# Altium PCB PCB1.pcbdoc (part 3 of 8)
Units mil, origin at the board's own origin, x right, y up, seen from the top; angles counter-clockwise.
Board outline 5129 x 4161 mil, 8 copper layers (Top Layer, GND1, 内层2, VCC, 内层4, Inner5, GND2, Bottom Layer); 495 components, 453 nets, 2562 pads, 1123 vias.

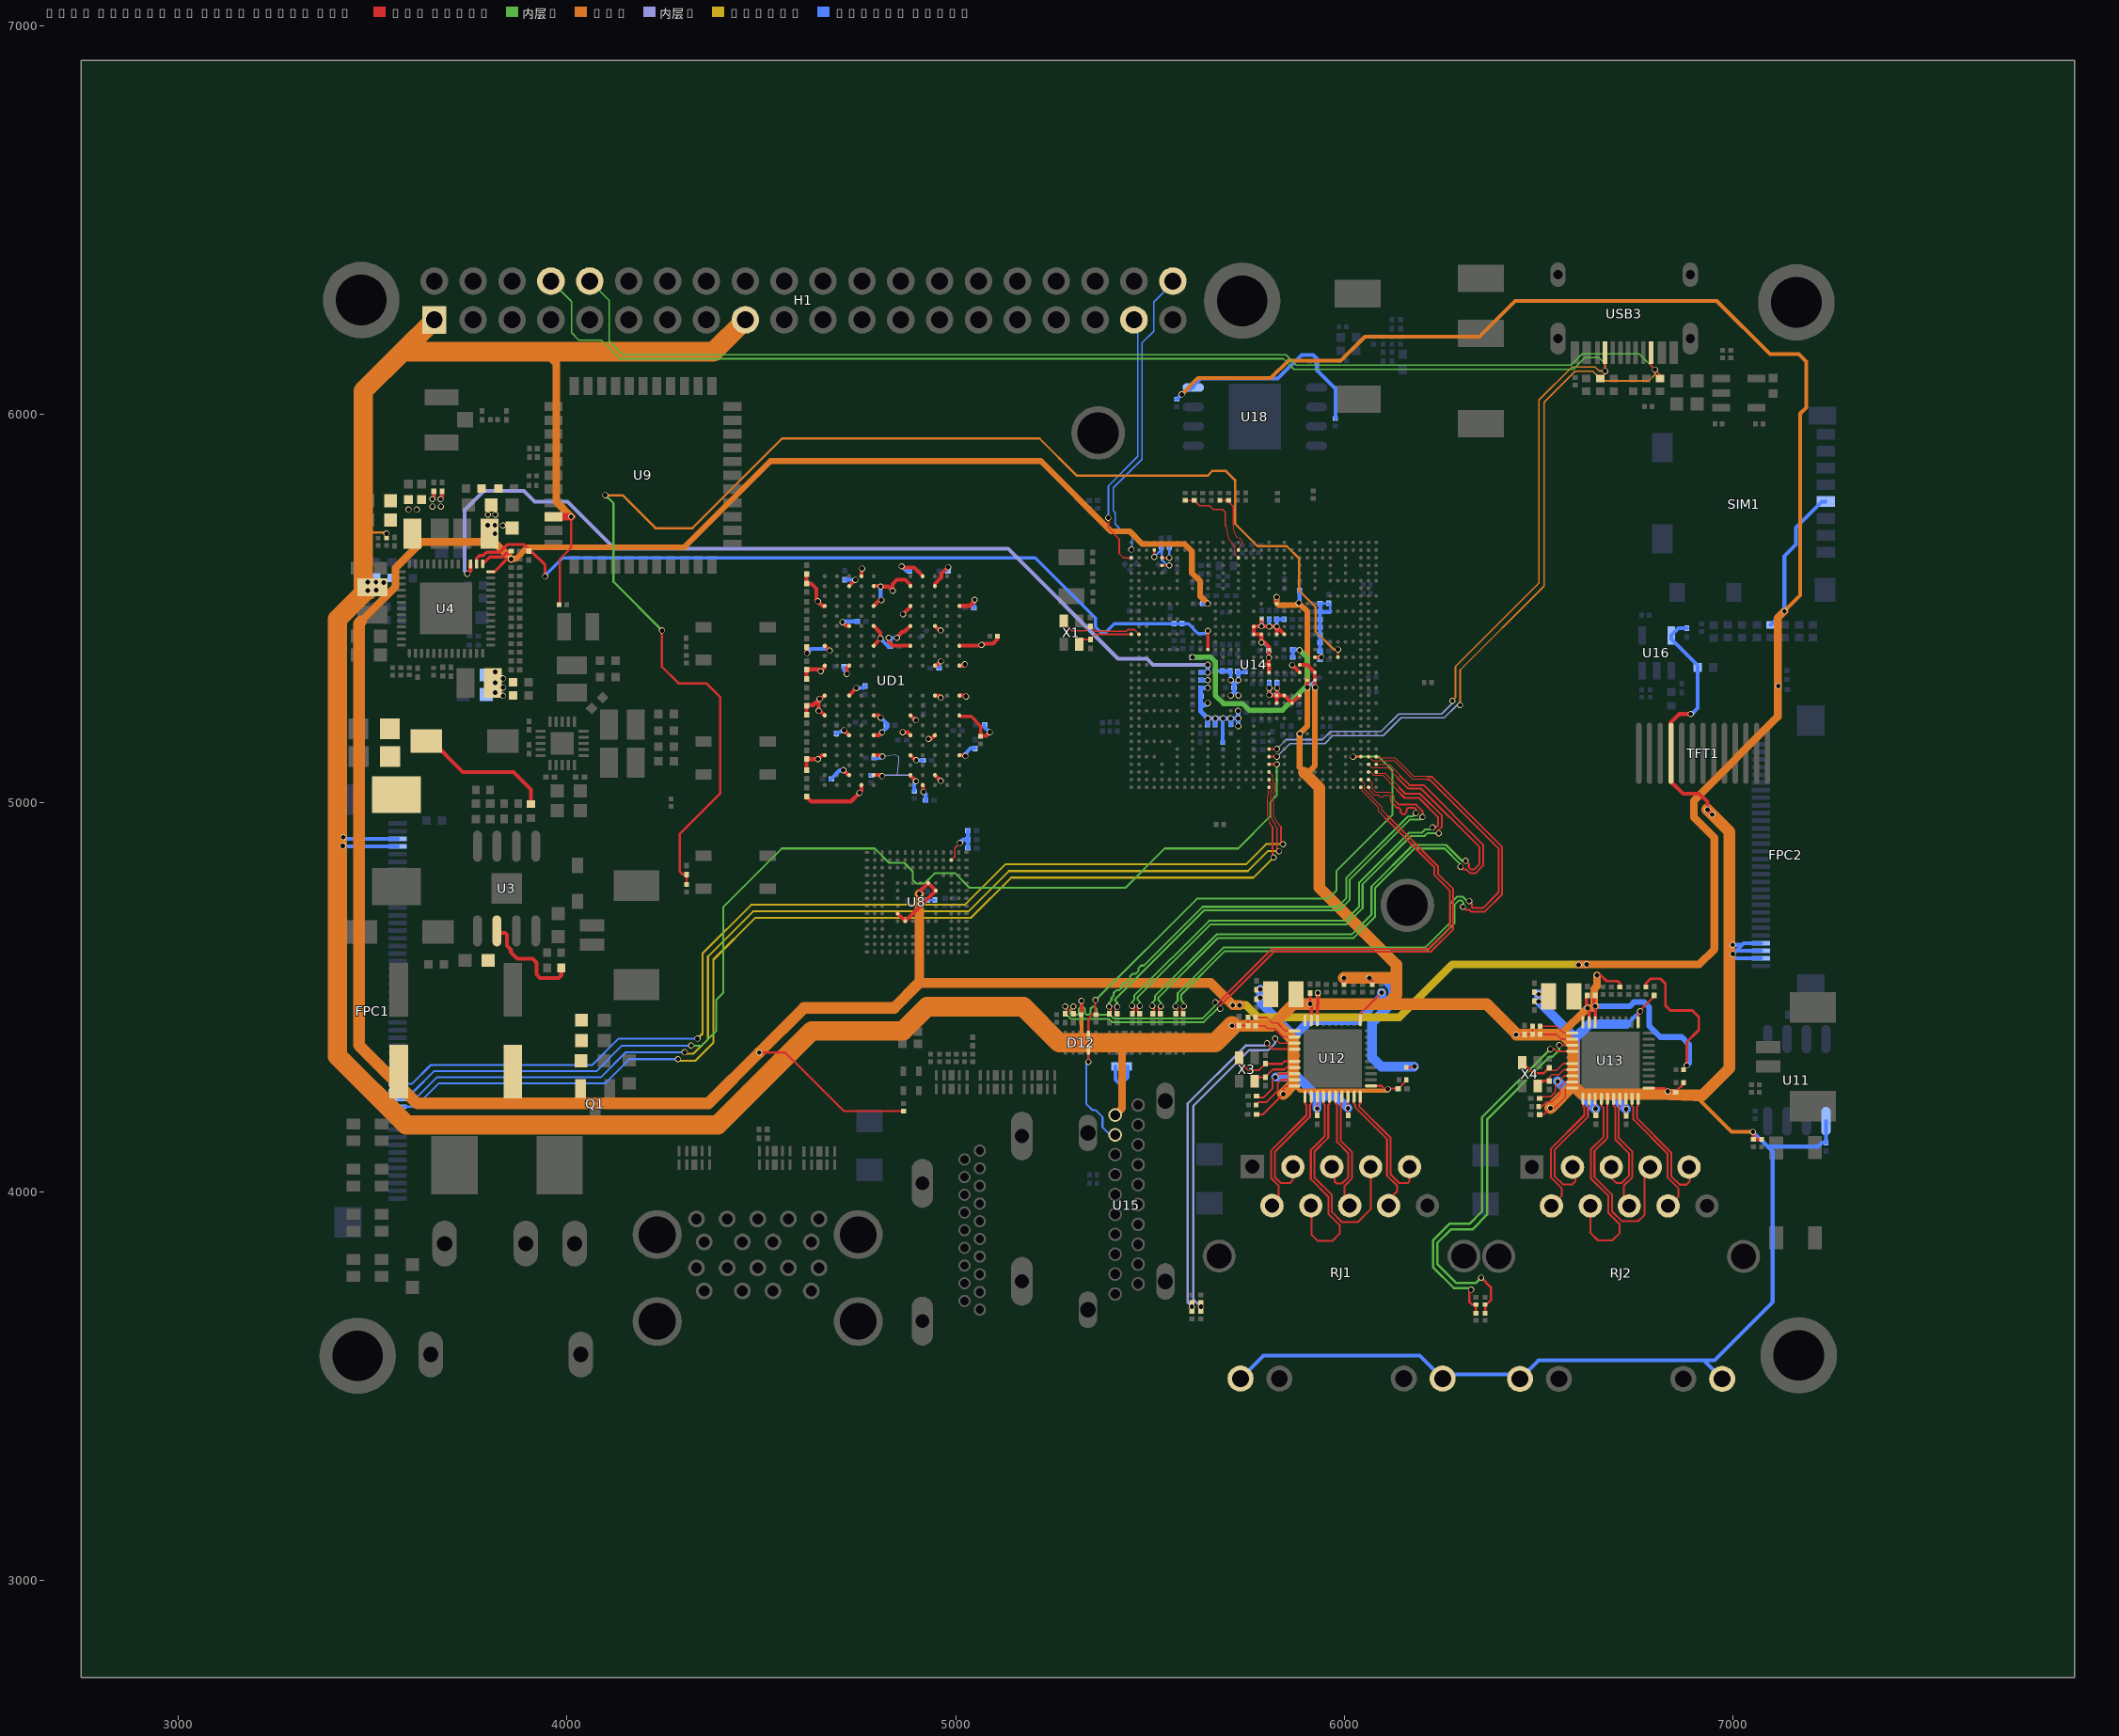
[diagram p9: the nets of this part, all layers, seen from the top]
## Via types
v1: diameter 15.75, hole 11.8, Top Layer to Bottom Layer, 496 vias
v2: diameter 15.7, hole 11.8, Top Layer to Bottom Layer, 335 vias
v3: diameter 15.75, hole 11.81, Top Layer to Bottom Layer, 279 vias
v4: diameter 24, hole 12, Top Layer to Bottom Layer, 13 vias

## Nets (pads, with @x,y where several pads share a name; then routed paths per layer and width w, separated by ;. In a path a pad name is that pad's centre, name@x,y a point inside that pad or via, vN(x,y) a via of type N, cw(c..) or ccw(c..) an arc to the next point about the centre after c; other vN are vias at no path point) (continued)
CLDO3: C64.2 C102.2 C228.1 C229.2 C230.2 C234.1 C235.2 C236.2 D20.1 R47.1 R73.2 R74.2 R75.2 SIM1.4 U4.26 U8.E6 U8.F5 U8.J10 U8.K9 U14.AC9 U18.8 | length 12994.8
  Top Layer w5: v2(4495,4358) 4562,4358 4712.51,4207.49 R47.1@4866,4207.49
  Top Layer w8: U4.26@3803.98,5594.97 3813.97,5594.97 3847,5628 v2(3856.5,5628)
  Top Layer w10: U8.K9@4850.78,4715.48 U8.J10@4870.48,4695.78 4945.65,4770.96 ; v2(4907,4766) 4907,4771.69 U8.F5@4929.52,4794.22 4945.65,4778.09 4945.65,4770.96 ; U8.E6@4949.22,4774.52 4945.65,4770.96
  VCC w10: v2(5581.59,6051.1) 5623.49,6093 5811,6093 5856,6138 5991,6138 6053,6200 6348,6200 6440,6292 6958,6292 7095,6155 7169,6155 7188,6136 7188,6017 7173,6002 7173,5534.4 v1(7132,5493.4)
  VCC w15: v2(3856.5,5628) 3869,5628 3899,5658 4302,5658 4524,5880 5219,5880 5400,5699 5448,5699 5481,5666 5589.33,5666 5608,5647.33 5608,5592 5629,5571 5629,5532.82 v2@5648.87,5512.95
  VCC w20: 3470,5467 3559,5556 3559,5605 3625.75,5671.75 3812.75,5671.75 v2(3856.5,5628) ; v2(6603,4584) 6604,4585 v2(6623.08,4585) 6913,4585 6952,4624 6952,4910 6899,4963 6899,5006 7115,5222 7115,5476.4 v1(7132,5493.4)
  VCC w25: v2(4907,4766) 4907,4538 4906,4537 5656,4537 v2(5713,4480) v2(5731,4480)
  VCC w30: 3470,5467 3465,5462 3465,4377 3615,4227 4364,4227 v2(4495,4358) 4610,4473 4842,4473 4906,4537
  Inner5 w20: v2(5713,4480) v2(5731,4480) 5747,4480 5778,4449 6142,4449 6278,4585 v2(6623.08,4585)
  Bottom Layer w6: v2(4907,4766) 4922.75,4750.25 C229.2@4927.75,4750.25 C235.2@4946.75,4750.25 ; v2(7116.5,5301) C228.1@7116.5,5318 C234.1@7116.5,5341
  Bottom Layer w10: C230.2@4899,4749 4899,4758 v2(4907,4766) ; R75.2@5569,6038.51 v2(5581.59,6051.1) 5599.49,6069 U18.8@5607,6069 ; U18.8@5603,6065 U18.8@5607,6069 ; U18.8@5611.23,6069 U18.8@5607,6069 ; C102.2@5636,5513 v2(5648.82,5513) ; R74.2@5977,5989.51 5977,6066 5929.51,6113.49 R73.2@5929.51,6135 5929.51,6143.49 5920,6153 5890,6153 5829,6092 5630,6092 U18.8@5607,6069 ; D20.1@7097,5458.4 v1(7132,5493.4) 7132,5635 7162,5665 7162,5709 7228.4,5775.4 SIM1.4@7238.14,5775.4
CLDO4: C66.2 U4.27 | length 86.4
  Top Layer w8: U4.27@3783.61,5615.33 3801.27,5633 3834,5633 3844,5643 3851.5,5643 C66.2@3856.5,5648
CPUSLDO: C13.1 C14.1 C35.2 U4.28 U14.AC15 | length 2148.2
  Top Layer w8: U4.28@3767.85,5615.33 3768,5615.49 3768,5630 3775,5637 3785,5637 3793,5645 3827,5645 3847,5665 3889.88,5665 3901,5653.88 3901,5649 C35.2@3902,5648 3908,5648 3944,5612 v2(3944,5583) ; U14.AC15@5648.87,5394.84 v2(5648.87,5443)
  Bottom Layer w8: v2(3944,5583) 3944,5586 3989,5631 5205,5631 5360,5476 5360,5453 5373,5440 5387,5440 5408,5461 5599,5461 5624,5436 5641.87,5436 v2(5648.87,5443)
CPUX-RX: D30.2 H1.10 U14.R29 USB3.B8 | length 4759
  Top Layer w5: U14.R29@5806.35,5119.25 v1(5826.35,5119.25) ; USB3.B8@6788.9,6158.7 6788.9,6125.1 v2(6799.2,6114.8) 6812,6102 D30.2@6812,6092.4
  内层2 w4: H1.10@4059,6343 4109,6293 4109,6188 4144,6153 5850,6153 5876,6127 6583,6127 6612,6156 6758,6156 v2@6799,6115
  VCC w4: v2(6298,5252) 6298,5342 6514,5558 6514,6031 6594,6111 6639,6111 6664,6086 6783,6086 6799.2,6102.2 v2(6799.2,6114.8)
  内层4 w4: v1(5826.35,5119.25) 5860.1,5153 5950,5153 5970,5173 6100,5173 6146,5219 6257,5219 6290,5252 v2(6298,5252)
CPUX-TX: D27.2 H1.8 U14.R28 USB3.A8 | length 4564.4
  Top Layer w5: U14.R28@5806.35,5138.93 v1(5826.35,5138.93) ; D27.2@6658,6092.4 6670.79,6105.19 USB3.A8@6670.79,6158.7
  内层2 w4: H1.8@3959,6343 4012,6290 4012,6210 4031,6191 4089,6191 4137,6143 5843,6143 5870,6116 6589,6116 6619,6146 6655,6146 6670.79,6130.21 v2(6670.79,6111.36)
  VCC w4: v2(6278,5263) 6286,5271 6286,5351 6501,5566 6501,6037 6586,6122 6645,6122 6655.64,6111.36 v2(6670.79,6111.36)
  内层4 w4: v1(5826.35,5138.93) 5850.43,5163 5944,5163 5965,5184 6095,5184 6140,5229 6250,5229 6278,5257 v2(6278,5263)
CPVDD: C105.2 U14.AJ3 | length 47
  Top Layer w6: U14.AJ3@5530.76,5631.06 v1(5549.76,5631.06)
  Bottom Layer w6: v1(5549.76,5631.06) 5549.76,5658.76 C105.2@5550,5659
CPVEE: C115.2 U14.AJ4 U14.AK2 | length 128.5
  Top Layer w6: v1(5511,5633) 5511,5650.68 U14.AK2@5511.07,5650.75 ; U14.AJ4@5530.76,5611.38 v1(5549.76,5611.38)
  Bottom Layer w6: v1(5511,5633) 5529,5651 C115.2@5529,5658.5 5531,5656.5 5531,5625 5544.62,5611.38 v1(5549.76,5611.38)
CTP-INT: FPC1.35 U14.R31 | length 2857.8
  Top Layer w3: U14.R31@5806.45,5080.07 5816.25,5070.27 5816.25,5053.78 5820.04,5049.99 ; 5819.83,5050.17 5820.04,5049.99 ; 5832.63,4943.08 5824.98,4953.82 5819.66,4962.85 5818.36,4968.27 5818.36,5028.09 5822.59,5032.31 5822.59,5038.2 5822.46,5039.1 5822.44,5041.94 5821.91,5048.12 ; 5820.04,5049.99 5821.89,5048.44 5821.91,5048.12 ; 5820.04,5049.99 5821.91,5048.12
  Top Layer w4: 5833,4943 5837,4939 5837,4899 v1(5842,4894)
  Inner5 w5: v1(4336,4394) 4349,4407 4349,4613 4474,4738 5024,4738 5128,4842 5747,4842 5799,4894 v1(5842,4894)
  Bottom Layer w5: FPC1.35@3564.97,4277.99 3601.99,4277.99 3650,4326 4065,4326 4133,4394 v1(4336,4394)
CTP-RST: FPC1.36 U14.R30 | length 2993
  Top Layer w5: U14.R30@5806.34,5099.56 v1(5826.34,5099.56)
  内层2 w5: v1(4320,4376) 4347,4376 4384,4413 4384,4493 4402,4511 4402,4732 4553,4883 4792.17,4883 4792.17,4882.83 4829,4846 4868,4846 4890,4824 4890,4802 4899,4793 4920,4793 4946,4819 4999,4819 5036,4782 5437,4782 5538,4883 5727,4883 5809,4965 5809,5002 5826.34,5019.34 v1(5826.34,5099.56)
  Bottom Layer w5: FPC1.36@3564.97,4258.31 3606.3,4258.31 3658,4310 4076,4310 4142,4376 v1(4320,4376)
CTP-SCK: FPC1.37 U14.R32 | length 2855.5
  Top Layer w3: 5806.31,5054.67 5810.33,5049.68 5815.64,5045.2 5815.94,5041.65 5815.99,5034.9 5811.36,5030.28 5811.36,4969.02 5813.9,4957.57 5821.16,4946.84 5824.94,4937.72 ; 5806.45,5054.57 U14.R32@5806.45,5060.37
  Top Layer w4: 5825,4937.64 5827,4935.64 5827,4881 v1(5832,4876)
  Inner5 w5: v1(4303,4359) 4307,4355 4326,4355 4363,4392 4363,4605 4479,4721 5033,4721 5137,4825 5752,4825 5803,4876 v1(5832,4876)
  Bottom Layer w5: FPC1.37@3564.97,4238.62 3609.62,4238.62 3666,4295 4088,4295 4152,4359 v1(4303,4359)
CTP-SDA: FPC1.38 U14.R33 | length 2832.6
  Top Layer w3: U14.R33@5805.67,5039.66 5803.57,5029.78 5803.88,5023.19 5801,5015.46 5801.46,5003.15 5801.31,4986.83 5801.77,4968.71 5808.16,4947.03
  Top Layer w4: 5807.95,4947.18 5812.64,4941.52 5815.32,4938.83 5815.32,4862.68 v1(5818,4860)
  Inner5 w5: v1(4286,4341) 4290,4337 4331,4337 4377,4383 4377,4597 4485,4705 5040,4705 5143,4808 5766,4808 v1(5818,4860)
  Bottom Layer w5: FPC1.38@3564.97,4218.94 3610.93,4218.94 3671,4279 4099,4279 4161,4341 v1(4286,4341)
DCDC1: C15.2 C16.2 C36.1 C37.1 C38.1 C39.1 C40.1 C41.1 C288.2 C289.2 L2.2 U14.W19 U14.W21 U14.Y19 U14.Y21 | length 182.7
  Bottom Layer w10: C40.1@5667,5339.5 5686.5,5339.5 C37.1@5686.75,5339.25 C36.1@5705.75,5339.25 5707.92,5337.08 v2(5707.92,5316.1) 5716.5,5307.52 5716.5,5304.99 ; v2(5707.92,5276.73) 5716.5,5285.3 5716.5,5287.83 ; C38.1@5725.53,5338.61 5727.61,5336.53 C38.1@5727.61,5336 ; v2(5727.61,5276.73) 5716.5,5287.83 ; C39.1@5745.11,5338.47 5742.64,5336 C38.1@5727.61,5336 ; 5716.5,5287.83 C41.1@5716.5,5297 5716.5,5304.99 ; 5716.5,5304.99 v2(5727.61,5316.1) C38.1@5727.61,5336
  other v1: 3836,5276 3816,5284.37 3836,5296.99 3816,5309 3836,5320.54 3816,5337
DCDC2: C18.2 C25.2 C47.1 C48.1 C49.1 C50.1 C57.1 C58.1 C67.1 C68.1 C75.1 C76.1 C77.1 C78.1 C210.2 C211.2 C213.2 C214.2 C215.2 C216.2 C218.2 C290.2 C291.2 L3.2 U14.J16 U14.L18 U14.L21 U14.M22 U14.N13 U14.N21 U14.P13 U14.P21 U14.P22 U14.R15 U14.R17 U14.R18 U14.T11 U14.T13 U14.U12 U14.U13 | length 964.7
  Top Layer w10: v1(3654,5782) 3658,5786 C210.2@3658,5802 ; v1(3675,5782) 3679,5786 C218.2@3679,5802 ; U14.T11@5786.67,5473.58 5786.67,5455.33 v1(5787,5455) ; v2(5787,5356) 5805.82,5356 U14.R17@5806,5355.82 ; U14.R18@5806.35,5335.78 U14.R17@5806.35,5355.47 U14.R17@5806,5355.82 ; v2(5807,5296) v2(5807,5278) 5808.27,5276.73 U14.P21@5826.04,5276.73 ; U14.P13@5826,5434.25 5826,5453.94 U14.N13@5845.72,5434.21 ; v1(5826,5454) v1(5807,5454) 5806,5455 v1(5787,5455) ; U14.P22@5826.04,5257.04 U14.P21@5826.04,5276.73 ; v2(5827,5296) 5827,5277.69 U14.P21@5826.04,5276.73 ; v2(5866,5355) 5866,5354.86 U14.L18@5885.09,5335.78 ; U14.L21@5885.09,5276.73 5865.41,5257.05 U14.N21@5845.72,5276.73 U14.P21@5826.04,5276.73 ; U14.J16@5924.46,5375.16 v2(5941,5375.16) ; v1(5787,5455) 5768.08,5455 U14.U12@5766.98,5453.9 U14.U13@5766.98,5434.21 U14.T13@5786.67,5434.21 5787,5433.88 v1(5787,5413) 5795,5413 5806.35,5401.65 U14.R15@5806.35,5394.84 5806,5394.49 v2(5806,5374) U14.R17@5806,5355.82
  Bottom Layer w6: C213.2@5938,5513 C214.2@5959,5513 ; C214.2@5960,5514 C214.2@5959,5513 ; 5963.5,5492 5963.5,5508.5 C214.2@5959,5513
  Bottom Layer w10: v1(5787,5413) 5793,5413 5805.5,5400.5 C47.1@5805.5,5392 5806,5391.5 v2(5806,5374) ; v1(5787,5455) 5787,5472.5 C77.1@5787.75,5473.25 ; C50.1@5806,5309.5 5807,5308.5 v2(5807,5296) v2(5807,5278) 5826.5,5278 C48.1@5827,5277.5 v2(5827,5296) C49.1@5827,5309.5 ; C78.1@5806.75,5473.25 5807,5473 v1(5807,5454) ; C76.1@5825.75,5473.25 C76.1@5826,5473 ; v1(5826,5454) C76.1@5826,5473 ; C75.1@5844.75,5473.25 5844.5,5473 C76.1@5826,5473 ; C58.1@5937.5,5369 5941,5372.5 v2(5941,5375.16) 5941,5387.5 C57.1@5937.5,5391 C67.1@5937.5,5413 C68.1@5937.5,5433 C215.2@5937.5,5452 C216.2@5937.5,5472 C211.2@5937.5,5491.5 ; C213.2@5938,5513 C211.2@5938,5492 C211.2@5937.5,5491.5 ; 5963.5,5492 5963,5491.5 C211.2@5937.5,5491.5
  other v1: 3593,5755 3614,5755 3654,5763 3676,5763
DCDC3: C31.2 C33.2 C116.1 C117.1 C118.2 C119.2 C120.2 C121.2 C122.2 C123.2 C124.2 C125.2 C126.2 C127.2 C128.2 C129.2 C130.2 C131.2 C142.1 C143.1 C144.2 C145.2 C146.2 C147.1 C148.2 C149.2 C150.2 C151.2 C152.2 C153.2 C154.2 C155.2 C156.2 C157.2 C158.2 C159.2 C160.2 C292.2 C293.2 L4.2 R36.2 R37.2 R38.2 R39.2 R40.2 U4.29 U14.AA24 U14.AB24 U14.AC17 U14.AC18 U14.AC19 U14.AC20 U14.AC22 U14.AC24 U14.W23 U14.W24 U14.W25 U14.Y24 UD1.A4 UD1.A9 UD1.AA3 UD1.AA5 UD1.AA8 UD1.AA10 UD1.AB4 UD1.AB9 UD1.B3 UD1.B5 UD1.B8 UD1.B10 UD1.D1 UD1.D5 UD1.D8 UD1.D12 UD1.F3 UD1.F5 UD1.F8 UD1.F10 UD1.H1 UD1.H5 UD1.H8 UD1.H12 UD1.K1 UD1.K3 UD1.K10 UD1.K12 UD1.N1 UD1.N3 UD1.N10 UD1.N12 UD1.R1 UD1.R5 UD1.R8 UD1.R12 UD1.U3 UD1.U5 UD1.U8 UD1.U10 UD1.W1 UD1.W5 UD1.W8 UD1.W12 | length 5468
  Top Layer w4.5: R37.2@5104.43,5428.97 5104.43,5424.36 R37.2@5104.87,5423.92
  Top Layer w8: UD1.H1@5009.63,5225.67 5012.33,5222.97 5040.03,5222.97 5064.92,5198.08 R36.2@5064.92,5172.81
  Top Layer w10: v1(3744,5590) 3752.1,5598.1 U4.29@3752.1,5615.33 ; C157.2@4616.92,5015.97 4628.92,5003.97 4730.84,5003.97 v3(4752.84,5025.97) 4757.66,5030.79 UD1.A9@4757.66,5046.54 ; C131.2@4616.92,5082.97 4616.92,5108.97 4620.92,5112.97 v3(4645.84,5112.97) 4656.18,5123.31 UD1.D12@4663.17,5123.31 ; C147.1@4616.92,5227.97 4616.92,5251.97 4633.92,5251.97 v3@4647.61,5265.66 ; C149.2@4616.92,5320.97 4616.92,5343.97 4647.92,5343.97 v3(4652.92,5338.97) 4663.17,5349.22 UD1.N12@4663.17,5353.63 ; C150.2@4616.92,5403.47 4616.92,5386.97 v3(4617.92,5385.97) ; C160.2@4616.92,5589.97 4616.92,5564.97 4628.3,5564.97 4641.92,5551.35 4641.92,5522.97 v3(4645.92,5518.97) 4657.72,5507.17 UD1.W12@4663.17,5507.17 ; v3@4647.02,5236.54 v3(4647.61,5237.13) ; UD1.H12@4663.17,5225.67 4651.71,5237.13 v3(4647.61,5237.13) ; UD1.K12@4663.17,5276.85 4654.29,5267.97 v3(4649.92,5267.97) v3@4647.61,5265.66 ; UD1.R12@4663.17,5404.81 v3(4675.97,5392.01) ; v3(4709.01,5465.47) 4718.49,5455.99 UD1.U10@4726.16,5455.99 ; v3(4711.26,5084.43) 4711.38,5084.43 4723.68,5072.13 UD1.B10@4726.16,5072.13 ; v3(4712.92,5186.97) 4725.4,5174.49 UD1.F10@4726.16,5174.49 ; v3(4720.47,5332.41) 4720.47,5347.94 UD1.N10@4726.16,5353.63 ; UD1.K10@4726.16,5276.85 4726.16,5277.21 v3(4744.92,5295.97) ; UD1.AA10@4726.16,5558.35 4741.78,5573.97 v3(4741.92,5573.97) ; UD1.AB9@4757.66,5583.94 4757.66,5601.57 v3(4759.28,5603.19) ; UD1.B8@4789.16,5072.13 4807.76,5072.13 v3(4810.92,5068.97) ; UD1.D8@4789.16,5123.31 4808.58,5123.31 v3(4811.92,5119.97) ; UD1.F8@4789.16,5174.49 4803.4,5174.49 v3(4810.85,5181.94) ; UD1.H8@4789.16,5225.67 4801.7,5225.67 v3(4807.57,5219.8) ; UD1.R8@4789.16,5404.81 4789.16,5405.29 4806.84,5422.97 v3(4806.84,5423.21) 4806.84,5438.31 UD1.U8@4789.16,5455.99 ; UD1.W8@4789.16,5507.17 4803.96,5521.97 v3(4808.92,5521.97) ; UD1.AA8@4789.16,5558.35 4805.54,5558.35 v3(4806.92,5556.97) 4826.92,5556.97 v3(4837.92,5545.97) 4837.92,5562.97 4848.94,5574 4870.58,5574 4883.64,5560.94 UD1.AA5@4883.64,5558.35 ; v3(4827.92,5424.97) 4827.92,5414.81 4837.92,5404.81 UD1.R5@4883.64,5404.81 ; v3(4848.92,5424.97) 4848.92,5425.97 4863.94,5441 4868.64,5441 UD1.U5@4883.64,5455.99 ; v3(4860.92,5608.97) 4863.92,5605.97 4893.11,5605.97 UD1.AB4@4915.14,5583.94 ; v3(4863.92,5181.97) 4876.16,5181.97 UD1.F5@4883.64,5174.49 ; v3(4864.92,5485.97) 4883.64,5504.69 UD1.W5@4883.64,5507.17 ; UD1.B5@4883.64,5072.13 4883.64,5070.25 v3(4897.92,5055.97) ; UD1.D5@4883.64,5123.31 4896.98,5109.97 v3(4898.92,5109.97) ; UD1.H5@4883.64,5225.67 4896.34,5212.97 4897.92,5212.97 4897.92,5212.83 v3(4898.08,5212.83) ; UD1.A4@4915.14,5046.54 4916.14,5045.54 4916.14,5033.75 4916.92,5032.97 4916.92,5029.41 v3(4917.61,5028.72) ; v3@4929.92,5164.94 4929.92,5162.97 4935.12,5162.97 UD1.F3@4946.64,5174.49 ; UD1.B3@4946.64,5072.13 4961.8,5056.97 v3(4961.92,5056.97) ; UD1.K3@4946.64,5276.85 4955.96,5276.85 v3(4961.84,5270.97) ; UD1.N3@4946.64,5353.63 4950.82,5353.63 v3(4962.16,5364.97) ; UD1.U3@4946.64,5455.99 4958.66,5443.97 v3(4961.92,5443.97) ; UD1.AA3@4946.64,5558.35 4946.64,5563.69 4962.92,5579.97 4962.92,5588.97 v3(4980.92,5606.97) ; UD1.D1@5009.63,5123.31 5022.58,5123.31 v3(5024.92,5120.97) ; UD1.K1@5009.63,5276.85 5023.96,5276.85 v3@5026.84,5273.97 ; UD1.N1@5009.63,5353.63 5020.63,5353.63 v3(5024,5357) ; UD1.R1@5009.63,5404.81 5064.75,5404.8 v3(5066.92,5406.97) 5070.08,5410.13 5096.08,5410.13 5106.92,5420.97 5106.92,5428.48 R37.2@5106.43,5428.97 ; UD1.W1@5009.63,5507.17 5036.82,5507.17 5048.92,5519.27 v3(5048.92,5522.97) ; R36.2@5064.92,5172.81 5078.76,5172.81 v3(5087.92,5181.97) ; v3(4647.61,5237.13) v3@4647.61,5265.66
  内层4 w3: v3(4811.92,5119.97) 4843,5125 4853,5120 4853,5109 4849.64,5072
  内层4 w4: v3(4810.92,5068.97) 4813.94,5072 4849.64,5072 4881.89,5072 v3(4897.92,5055.97)
  内层4 w10: v1(3744,5590) 3737,5597 3737,5753 3787,5803 3889,5803 3917,5775 4002,5775 4123,5654 5135,5654 5418,5371 5492,5371 5507.58,5355.42 v3(5648.55,5355.42)
  Bottom Layer w8: C156.2@4712.92,5348.97 4712.92,5339.96 v3(4720.47,5332.41) ; v3(4827.92,5424.97) v3(4848.92,5424.97) ; C121.2@4957.92,5345.97 4957.92,5360.73 v3(4962.16,5364.97) ; C125.2@4978.78,5598.2 4978.78,5604.84 v3(4980.92,5606.97)
  Bottom Layer w10: v3(4617.92,5385.97) 4628.94,5397 4670.98,5397 v3(4675.97,5392.01) ; C116.1@4678.5,5060.67 4701.8,5083.97 4710.8,5083.97 v3(4711.26,5084.43) ; C117.1@4693,5178.5 v3(4712.92,5186.97) ; v3(4709.01,5465.47) 4710.85,5467.31 C130.2@4749.12,5467.31 ; C143.1@4715.92,5573.97 v3(4741.92,5573.97) ; v3(4744.92,5295.97) 4763.08,5295.97 C142.1@4767.92,5300.81 ; R40.2@4782.21,5072.13 4807.76,5072.13 v3(4810.92,5068.97) ; C124.2@4788.76,5115.97 4807.92,5115.97 v3(4811.92,5119.97) ; v3(4806.84,5423.21) 4827.37,5402.68 4833.12,5402.68 4833.12,5419.77 v3(4827.92,5424.97) ; v3(4806.92,5556.97) 4806.92,5523.97 v3(4808.92,5521.97) ; v3(4807.57,5219.8) 4824.08,5203.29 4824.08,5195.17 v3(4810.85,5181.94) ; v3(4860.92,5608.97) 4872.92,5596.97 C144.2@4884.08,5596.97 ; R39.2@4893.92,5032.81 4893.92,5051.97 v3(4897.92,5055.97) ; v3(4898.92,5109.97) C118.2@4914.92,5109.97 ; v3(4917.61,5028.72) 4923.26,5023.07 C152.2@4923.26,5006.06 ; v3(5024.92,5120.97) 5024.92,5126.97 5039.08,5141.13 C123.2@5048.92,5141.13 ; C145.2@5047.42,5501.97 5047.42,5521.47 v3(5048.92,5522.97) ; C122.2@5073.76,5200.97 5073.76,5196.13 v3(5087.92,5181.97) ; R38.2@5687,5155.51 5687,5216.7 v3(5687.92,5217.62)
  Bottom Layer w12: C154.2@5630,5316 v3(5648.55,5316.05) ; C128.2@5630,5336 5648.28,5336 5648.55,5335.73 v3(5648.55,5355.42) ; C155.2@5648,5202 5648.55,5202.55 v3(5648.55,5217.62) ; v3(5648.55,5256.99) 5643.55,5252 C126.2@5630.5,5252 ; v3(5648.55,5296.36) 5648.2,5296 5630,5296 5630,5275 5630,5252.5 C126.2@5630.5,5252 ; C119.2@5668,5202 5668.23,5202.23 v3(5668.23,5217.62) ; C129.2@5708,5201 5708,5217.22 v3(5707.6,5217.62) ; v3(5727,5237) 5727.29,5236.71 v3(5727.29,5217.62) ; v3(5727.3,5197.94) v3(5727.29,5217.62) ; C126.2@5630.5,5252 5630.5,5235.66 v3(5648.55,5217.62) ; v3(5648.55,5217.62) v3(5668.23,5217.62) ; v3(5668.23,5217.62) v3(5687.92,5217.62) v3(5707.6,5217.62) ; v3(5707.6,5217.62) v3(5727.29,5217.62)
  other v1: 3815.02,5693 3835,5714 3796,5715 3815,5715 3797,5742 3816,5742
  other v3: 4929.85,5164.94 5026.92,5273.97 5648.55,5335.73
DCIN-5V: C5.2 C6.2 D3.1 L1.2 R3.2 | length 359.3
  Top Layer w10: D3.1@3638.43,5160 3652.57,5160 3732.57,5080 3863,5080 3908,5035 R3.2@3908,4997
DCIN-12V: C1.2 C2.2 C7.2 Q1.2 R1.2 R4.2 U1.1 U2.1 U3.2 | length 294.6
  Top Layer w10: U3.2@3820,4652 U3.2@3820,4670.98 3824.98,4666 3841,4666 3846,4661 3846,4633 3856,4623 3856,4616 3873,4599 3912,4599 3922,4589 3922,4559 3931,4550 3979,4550 3985.45,4556.45 R4.2@3985.45,4575.77
DCXO-XIN: C99.2 U14.AM13 X1.1 | length 224.2
  Top Layer w4: X1.1@5278,5468.46 5278,5463.76 5299,5442.76 5333.96,5442.76 C99.2@5346.35,5455.15 5359.49,5442 5439,5442 5443,5446 5459.91,5446 U14.AM13@5471.7,5434.21
DCXO-XOUT: C98.2 U14.AN13 X1.3 | length 144.7
  Top Layer w4: X1.3@5318,5408.46 5330.29,5420.76 C98.2@5347,5420.76 5360.46,5434.21 U14.AN13@5452.02,5434.21
DDR-PARA-SEL-ADC1: R31.1 R34.2 U14.W2 | length 168.2
  Top Layer w3: 5713.91,5717.67 5717.23,5700.13 5724.34,5682.99 5731.68,5681.44 5737.24,5673.79 5737.3,5666.34 5727.49,5656.53 U14.W2@5727.49,5650.71
  Top Layer w4: R34.2@5680,5778.49 R31.1@5702,5778.49 5702,5775 5714,5763 5714,5717.81
DDR-PARA-SEL-ADC2: R32.1 R35.2 U14.W3 | length 243.1
  Top Layer w3: 5696.07,5712.34 5696.1,5712.2 5703.04,5679.34 5717.45,5658.68 5717.68,5640.82 U14.W3@5727.49,5631.01
  Top Layer w4: R32.1@5591,5778.49 R35.2@5614,5778.49 5627.49,5765 5653,5765 5663,5755 5687,5755 5694,5748 5694,5714.3 5696.1,5712.2 5696.23,5712.07
DSP-UART-RX: H1.40 U14.AN2 | length 782.9
  Bottom Layer w4: v2(5452,5652) 5454,5654 5454,5688 5445,5697 5431.61,5697 5411,5717.61 5411,5747 5406,5752 5406,5811 5480,5885 5480,6184 5510,6214 5510,6289 5559,6338 H1.40@5559,6343
DSP-UART-TX: H1.37 U14.AN3 | length 687.2
  Top Layer w4: v2(5393,5734) 5393,5707 5421,5679 5421,5642 5431.94,5631.06 U14.AN3@5452.02,5631.06
  Bottom Layer w4: v2(5393,5734) 5393,5816 5469,5892 5469,6005.57 ; H1.37@5459,6243 5469,6233 5469,6005.57 ; 5469,6009 5469,6005.57
EDP-AUXN: C199.1 U14.C33 | length 1642.4
  Top Layer w3: U14.C33@6042.49,5040.4 6044.28,5038.61 6044.28,5032.46 6088,4988.74 6088,4979 6106,4961 6106,4960
  Top Layer w5: C199.1@5303,4457.5 5299,4461.5 5299,4472.5 v1(5303,4476.5) ; v1(5668,4487) 5676.25,4487 5814.25,4625 6217,4625 6271,4679 6271,4775.25 6232,4814.25 6232,4834 6106,4960
  内层2 w5: v1(5303,4476.5) 5295,4468.5 5295,4460 5300,4455 5312.28,4455 5317.28,4460 5317.28,4471 5322.28,4476 5327.28,4476 5332.28,4471 5332.28,4460 5337.28,4455 5342.28,4455 5347.28,4460 5347.28,4471 5352.28,4476 5357.28,4476 5362.28,4471 5362.28,4460 5367.28,4455 5397,4455 5406.62,4445.38 5634.62,4445.38 5668,4478.75 v1(5668,4487)
EDP-AUXP: C198.1 U14.C32 | length 1635.2
  Top Layer w3: U14.C32@6042.49,5060.11 6052.29,5050.31 6052.29,5036.35 6051.78,5035.84 6051.79,5034.86 6097,4989.65 6097,4981.75 6112.38,4966.38
  Top Layer w5: C198.1@5282,4457.5 5286,4461.5 5286,4472.5 v1(5282,4476.5) ; v1(5681,4471) 5681,4479 5819,4617 6221.75,4617 6280.02,4675.27 6280.02,4778.98 6241.02,4817.98 6241.02,4837.73 6112.38,4966.38
  内层2 w5: v1(5282,4476.5) 5285.98,4472.52 5285.98,4455.27 5297.25,4444 5395.25,4444 5402.89,4436.36 5638.36,4436.36 5674,4472 5680,4472 v1(5681,4471)
EDP-HPD: D12.4 D12.7 R60.2 U14.C29 U15.18 | length 1646.6
  Top Layer w5: v1(5341.7,4334) D12.4@5341.7,4365.67 D12.7@5341.7,4400.33 5341.7,4444.7 5354,4457 R60.2@5359.51,4457 ; v1(5360,4493) 5359.51,4492.51 R60.2@5359.51,4457 ; R60.2@5361,4455.51 R60.2@5359.51,4457 ; v1(6022.57,5119.25) U14.C29@6042.57,5119.25
  内层2 w5: v1(5360,4493) 5621,4754 5959,4754 5980,4775 5980,4826 6124,4970 6124,5084 6088.75,5119.25 v1(6022.57,5119.25)
  Bottom Layer w5: v1(5341.7,4334) 5336,4328.3 5336,4226 5352,4210 5360,4210 5378,4192 5378,4166 5397.8,4146.2 U15.18@5410.5,4146.2
EDP-TX0N: C191.1 U14.B29 | length 1595.3
  Top Layer w3: U14.B29@6062.19,5119.21 6072.01,5109.39 6127.61,5109.39 6176,5061 6213,5061 6214,5060
  Top Layer w5: v1(5566,4477) 5570,4473 5570,4461 C191.1@5566.6,4457.6 ; 6214,5060 6220,5060 6397,4883 6397,4770 6356.63,4729.63 6330.23,4729.63 6328.47,4731.4 6328.47,4740.59 v1(6321.13,4747.92)
  内层2 w5: v1(5566,4477) 5566,4486.37 5571.6,4491.97 5571.6,4510.35 5689.27,4628.02 6208.29,4628.02 6273,4692.73 6273,4742 6290,4759 6305,4759 6316.08,4747.92 v1(6321.13,4747.92)
EDP-TX0P: C190.1 U14.A29 | length 1590.8
  Top Layer w3: U14.A29@6081.89,5119.21 6084.71,5116.39 6130.61,5116.39 6179,5068 6213,5068
  Top Layer w5: C190.1@5585.6,4457.6 5582,4461.21 5582,4472 v1(5587,4477) ; 6213,5068 6224.73,5068 6406,4886.73 6406,4765 6361.63,4720.63 6326.51,4720.63 6322.1,4725.03 6312.91,4725.03 v1(6304.87,4733.08)
  内层2 w5: v1(5587,4477) 5587,4485.58 5580.61,4491.97 5580.61,4506.61 5693,4619 6212,4619 6283,4690 6283,4738 6294,4749 6302,4749 6307,4744 6307,4735.21 v1(6304.87,4733.08)
EDP-TX1N: C193.1 U14.B30 | length 1542
  Top Layer w3: U14.B30@6062.19,5099.51 6071.7,5090 6113,5090 6134.5,5068.5 6134.5,5067.5
  Top Layer w5: v1(5506,4478) 5511,4473 5511,4461 C193.1@5507.6,4457.6 ; 6136.64,5064.64 6164.27,5037 6197.59,5037 6348,4886.59 6348,4843 6333.72,4828.72 6326.65,4828.72 6320.34,4835.03 6320.34,4842.66 v1(6312,4851)
  内层2 w5: v1(5506,4478) 5506,4486.37 5512.6,4492.97 5512.6,4503.35 5671.27,4662.02 6019.02,4662.02 6070,4713 6070,4785 6177.02,4892.02 6261.73,4892.02 6302.75,4851 v1(6312,4851)
EDP-TX1P: C192.1 U14.A30 | length 1534.9
  Top Layer w3: U14.A30@6081.94,5099.55 6083.49,5098 6116.73,5098 6140.86,5073.86
  Top Layer w5: C192.1@5526.6,4457.6 5523,4461.21 5523,4472 v1(5528,4477) ; 6143,5071 6168,5046 6204,5046 6357,4893 6357,4839 6337,4819 6323.64,4819 6313.97,4828.66 6306.34,4828.66 v1(6299,4836)
  内层2 w5: v1(5528,4477) 5528,4486.58 5521.61,4492.97 5521.61,4499.61 5675,4653 6024,4653 6079,4708 6079,4781.25 6180.75,4883 6258,4883 6299,4842 v1(6299,4836)
EDP-TX2N: C195.1 U14.B31 | length 1301.6
  Top Layer w3: U14.B31@6062.19,5079.81 6067.41,5079.81 6077.21,5070.01 6100,5070.01 6134,5036 6134,5034.27 6135.64,5032.64
  Top Layer w5: v1(5454,4478) 5459,4473 5459,4462 C195.1@5454.6,4457.6 ; 6135.64,5032.64 6155.27,5013 6192,5013 6241,4964 6241,4942 6236,4937 v2(6227,4937)
  内层2 w5: v1(5454,4478) 5454,4488.37 5459.49,4493.87 5459.49,4504.24 5652.27,4697.02 6002.02,4697.02 6038,4733 6038,4794.73 6167.28,4924.02 6200.02,4924.02 6208,4932 6222,4932 v2(6227,4937)
EDP-TX2P: C194.1 U14.A31 | length 1303.9
  Top Layer w3: U14.A31@6081.89,5079.81 6084.69,5077.01 6104.67,5077.01 6142,5039.75 6142,5039
  Top Layer w5: v1@5470.61,4478 v1(5474,4478) 5468.02,4472.02 5468.02,4463.19 C194.1@5473.6,4457.6 ; 6142,5039 6157,5024 6195,5024 6251,4968 6251,4939.14 6243,4931.14 v2(6243,4922)
  内层2 w5: v1(5474,4478) 5474,4488.37 5468.51,4493.87 5468.51,4500.51 5656,4688 6006,4688 6047,4729 6047,4790.98 6171.02,4915 6206,4915 6213,4922 v2(6243,4922)
EDP-TX3N: C197.1 U14.B33 | length 1264.8
  Top Layer w3: U14.B33@6062.19,5040.41 6065.09,5037.51 6065.09,5033.45 6077.52,5021.02 6087.2,5021.02 6092.2,5016.02 6099.2,5016.02 6103.18,5020 6116,5020 6119.98,5016.02 6119.98,5003.29 6127.64,4995.64
  Top Layer w4: v1(5395,4476) 5400,4471 5400,4462 C197.1@5395.6,4457.6
  Top Layer w5: 6127.64,4995.64 6135.27,4988 6140,4988 6145,4983 6145,4976 6150,4971 6155,4971 6160,4976 6160,4983 6165,4988 6180,4988 6184,4984 v2(6184,4974)
  内层2 w5: v1(5395,4476) 5395,4486.37 5400.99,4492.37 5400.99,4498.6 5406.4,4504.01 5406.4,4511.08 5413.47,4518.15 5420.54,4518.15 5427.62,4525.22 5427.62,4532.3 5434.69,4539.37 5441.76,4539.37 5448.83,4546.44 5448.83,4553.51 5455.9,4560.58 5462.97,4560.58 5470.04,4567.65 5470.04,4574.72 5477.11,4581.79 5484.18,4581.79 5635.41,4733.02 5983.02,4733.02 6005,4755 6005,4806.75 6164.25,4966 6176,4966 v2(6184,4974)
EDP-TX3P: C196.1 U14.B32 | length 1261.6
  Top Layer w3: U14.B32@6062.19,5060.11 6072.2,5050.1 6072.2,5044.58 6072.09,5044.47 6072.09,5036.35 6080.42,5028.02 6118.1,5028.02 6127,5019.12 6127,5019 6129,5017 6129,5007 6134,5002
  Top Layer w4: C196.1@5415.6,4457.6 5411,4462.21 5411,4471 v1(5416,4476)
  Top Layer w5: 6134,5002 6140,4996 6185,4996 6201,4980 v2(6201,4964)
  内层2 w5: v1(5416,4476) 5416,4486.37 5410.01,4492.37 5410.01,4494.87 5639.14,4724 5987,4724 6014,4751 6014,4803 6168,4957 6194,4957 v2(6201,4964)
EMMC-VDDI: C231.1 C232.2 C233.2 U8.C2 | length 122.7
  Top Layer w4: U8.C2@4988.59,4853.27 4998,4862.68 4998,4884 v1(5011,4897)
  Bottom Layer w10: v1(5011,4897) 5020,4906 C232.2@5032,4906 ; C233.2@5032,4884 C232.2@5032,4906 ; C231.1@5032,4929 C232.2@5032,4906
FEL: C96.2 R22.2 U14.F16 | length 3642.7
  Top Layer w5: U14.F16@5983.52,5375.16 v1(5983.52,5395.16)
  Top Layer w6: v2(4245,5444) 4245,5350 4287,5308 4359,5308 4394,5273 4394,5024 4290,4920 4290,4824.62 4298.62,4816 C96.2@4308,4816 R22.2@4308,4790.51
  内层2 w6: v2(4099,5792) 4120,5771 4120,5569 v2(4245,5444)
  VCC w6: v2(4099,5792) 4143,5792 4228,5707 4323,5707 4554,5938 5216,5938 5312,5842 5648,5842 5660,5854 5696,5854 5719,5831 5719,5719 5777,5661 5852,5661 5884,5629 5884,5546 5926,5504 5926,5441.81 5972.64,5395.16 v1(5983.52,5395.16)
GM0_DVDD10: C253.1 C254.1 C265.1 C266.1 C267.1 C268.2 L9.2 U12.3 U12.8 U12.21 U12.38 | length 1119.3
  Top Layer w5: C265.1@5772.5,4246 5776.5,4242 5792,4242 5815,4265 5815,4287 v1(5822.89,4294.89) 5831.6,4303.6 U12.38@5871.6,4303.6 ; C267.1@5930,4196.5 v1(5930,4214) 5930,4244 U12.3@5930.6,4244.6 ; U12.8@6009.4,4244.6 v1(6009.4,4215) 6009.4,4197.1 C266.1@6010,4196.5 ; U12.21@6040.9,4441.4 6040.9,4456.9 6096,4512 v1(6096,4512.5)
  Bottom Layer w23: v1(5784,4521) v1(5784,4499) 5784,4487 5872,4399 5872,4313.21 ; v1(5822.89,4294.89) 5853.67,4294.89 5872,4313.21 ; 5874,4403 5911,4440 6034,4440 6096,4502 v1(6096,4512.5) ; v1(5930,4214) 5930,4245 ; v1(6009.4,4215) 5979.4,4245 5930,4245 ; 5872,4313.21 5872,4303 5930,4245
GM0_INTB: R88.2 U12.31 | length 114.6
  Top Layer w4: R88.2@5771.51,4449 5772.51,4448 5801,4448 5815,4434 5828,4434 5848.1,4413.9 U12.31@5871.6,4413.9
GM0_LED0: R92.1 U12.32 | length 112.1
  Top Layer w4: R92.1@5771.51,4427 5795.51,4427 5802.51,4420 5821,4420 5842.9,4398.1 U12.32@5871.6,4398.1
GM0_LED1: R80.2 R94.2 U12.33 | length 892.8
  Top Layer w4: v2(5822,4394) 5833.6,4382.4 U12.33@5871.6,4382.4
  Top Layer w6: R80.2@5631,3691.51 v2(5631,3703.92) R94.2@5631,3715.49
  内层4 w6: v2(5631,3703.92) 5611,3723.92 5611,4220 5755,4364 5804,4364 5822,4382 v2(5822,4394)
GM0_LED2: R79.1 R96.2 U12.34 | length 897
  Top Layer w5: v2(5801,4382) 5816.4,4366.6 U12.34@5871.6,4366.6
  Top Layer w6: R79.1@5608,3691.51 v2(5608,3703.69) R96.2@5608,3715.49
  内层4 w6: v2(5608,3703.69) 5597,3714.69 5597,4227 5746,4376 5795,4376 v2(5801,4382)
GM0_MDIN0: RJ1.P3 U12.2 | length 336.5
  Top Layer w5: RJ1.P3@5867.8,4064.16 5867.8,4029.8 5860,4022 5837,4022 5821,4038 5821,4102.25 5911.51,4192.76 5911.51,4222.96 5914.9,4226.35 U12.2@5914.9,4244.6
GM0_MDIN1: RJ1.P7 U12.5 | length 564.9
  Top Layer w5: U12.5@5962.1,4244.6 5962.1,4226.35 5958.76,4223.01 5958.76,4139.01 5923,4103.25 5923,4036 5968.02,3990.98 5968.02,3947.98 5994,3922 6035,3922 6067.8,3954.8 RJ1.P7@6067.8,4064.16
GM0_MDIN2: RJ1.P6 U12.7 | length 307.6
  Top Layer w5: U12.7@5993.6,4244.6 5993.6,4226.35 5990.26,4223.01 5990.26,4131.74 6019.64,4102.36 6019.64,4033.89 6000.38,4014.62 6000.38,3977.68 RJ1.P6@6013.9,3964.16
GM0_MDIN3: RJ1.P9 U12.10 | length 332.4
  Top Layer w5: U12.10@6040.9,4244.6 6040.9,4226.35 6037.51,4222.96 6037.51,4220.46 6119,4138.97 6119,4045 6142,4022 6163,4022 6167.8,4026.8 RJ1.P9@6167.8,4064.16
GM0_MDIP0: RJ1.P2 U12.1 | length 334
  Top Layer w5: RJ1.P2@5813.9,3964.16 5830.62,3980.88 5830.62,4015.62 5811.98,4034.27 5811.98,4105.98 5902.49,4196.49 5902.49,4222.96 5899.1,4226.35 U12.1@5899.1,4244.6
GM0_MDIP1: RJ1.P4 U12.4 | length 562
  Top Layer w5: RJ1.P4@5913.9,3964.16 5916,3962.06 5916,3889 5932,3873 5969,3873 5988,3892 5988,3914 5959,3943 5959,3987.25 5913.98,4032.27 5913.98,4106.98 5949.74,4142.74 5949.74,4223.01 5946.4,4226.35 U12.4@5946.4,4244.6
GM0_MDIP2: RJ1.P5 U12.6 | length 306.3
  Top Layer w5: RJ1.P5@5967.8,4064.16 5975,4056.96 5975,4026 5980,4021 5994,4021 6010.62,4037.62 6010.62,4098.62 5981.24,4128.01 5981.24,4223.01 5977.9,4226.35 U12.6@5977.9,4244.6
GM0_MDIP3: RJ1.P8 U12.9 | length 335.5
  Top Layer w5: U12.9@6025.1,4244.6 6025.1,4226.35 6028.49,4222.96 6028.49,4216.73 6109.98,4135.23 6109.98,4041.27 6136,4015.25 6136,4001 6113.9,3978.9 RJ1.P8@6113.9,3964.16
GM0_REGOUT: L9.1 U12.30
GM0_RSET: R85.2 U12.39 | length 137.4
  Top Layer w5: R85.2@5772.51,4223 5779.51,4230 5799,4230 5829,4260 5829,4279.49 5837.41,4287.9 U12.39@5871.6,4287.9
GM0_XTAL_IN: C252.2 U12.36 X3.1 | length 167.3
  Top Layer w5: X3.1@5729,4342 5729,4336 5752,4313 5781,4313 C252.2@5797,4329 5840,4329 5846.1,4335.1 U12.36@5871.6,4335.1
GM0_XTAL_OUT: C251.2 U12.37 X3.3 | length 118.1
  Top Layer w5: X3.3@5769,4282 5782,4295 C251.2@5797,4295 5816.4,4314.4 5846.4,4314.4 5851.4,4319.4 U12.37@5871.6,4319.4
GM1_DVDD10: C260.1 C261.1 C272.1 C273.1 C274.1 C275.2 L10.2 U13.3 U13.8 U13.21 U13.38 | length 1030.9
  Top Layer w4: C273.1@6502.5,4240 6506.5,4244 6531,4244 6543,4256 6543,4275 6566.11,4298.11 U13.38@6586.51,4298.11
  Top Layer w5: U13.3@6645.51,4239.11 6646,4238.62 v1(6646,4213) 6646,4197 C275.2@6647,4196 ; U13.8@6724.31,4239.11 6725,4238.42 v1(6725,4212.42) C272.1@6725,4195.5
  Top Layer w6: U13.21@6755.81,4435.91 6755.81,4461.31 C274.1@6800,4505.5
  Bottom Layer w10: 6726,4431 ccw(c6182.51,5042.49) v1(6761,4464)
  Bottom Layer w25: v1(6500,4508) v1(6500,4489.39) 6594,4395.39 ; v1(6549,4284) 6568,4265 6594,4265 ; v1(6646,4213) 6608,4251 ; v1(6725,4212.42) 6686.42,4251 6608,4251 ; 6726,4431 6629.61,4431 6594,4395.39 ; 6594,4265 6594,4395.39 ; 6594,4265 6608,4251
GM1_DVDDRG: C32.1 C34.1 C42.1 C167.2 C168.2 C169.2 C170.2 C173.2 C174.2 C175.2 C176.2 C177.2 C178.2 C200.2 C204.2 C223.2 C224.2 C249.1 C250.1 C256.1 C258.1 C262.1 C263.1 C264.1 C269.1 C270.1 C271.1 C276.1 FPC1.3 FPC1.4 FPC2.2 FPC2.3 FPC2.4 H1.1 H1.17 L5.1 R14.1 R17.2 R61.1 R83.1 R88.1 R89.2 R90.1 R91.2 R92.2 R101.1 R106.1 R107.2 R108.1 R109.2 R110.2 R124.2 R125.2 RJ1.11 RJ1.14 RJ2.11 RJ2.14 TFT1.10 U9.9 U11.5 U12.11 U12.28 U12.29 U12.40 U13.11 U13.28 U13.29 U13.40 U14.AE16 U14.J18 U14.J19 U14.K19 U14.L9 U14.L15 U14.L17 U14.L26 U14.P9 U15.20 U16.5 | length 18139.1
  Top Layer w4: v1(6442,4404) 6463.5,4404 C271.1@6464,4404.5 6483.99,4404.5 R110.2@6484.49,4405 R106.1@6484.49,4426 ; C269.1@6502.5,4198 6513,4198 v1(6530,4215) 6540,4215 6568,4243 6568,4263 6571.61,4266.61 U13.40@6586.51,4266.61 ; R101.1@6872.51,4314 6881,4322.49 v1(6881,4325)
  Top Layer w5: C263.1@5729,4427.5 R92.2@5748.97,4427.5 ; R88.1@5752.49,4449 R92.2@5752.49,4431.02 ; C262.1@5774,4199 5791,4199 v2(5843,4251) 5843,4265 5850.1,4272.1 U12.40@5871.6,4272.1 ; U12.11@6068.4,4272.1 6095.9,4272.1 6103,4265 C264.1@6138.5,4265 6159.51,4286.01 R90.1@6159.51,4288 ; R83.1@6159.51,4320 6179,4320 v1(6181,4322) ; R92.2@5748.97,4427.5 R92.2@5752.49,4431.02 ; R92.2@5748.97,4427.5 5751.99,4427.5 R92.2@5752.49,4427 R92.2@5752.49,4431.02
  Top Layer w6: R17.2@3980.49,5510 3982,5511.51 3982,5628 4011,5657 v2(4011,5736.7) ; U14.P9@5826.04,5512.95 v1(5826.04,5529.95) ; R89.2@5998,4533.51 R89.2@5999,4532.51 ; U13.11@6783.31,4266.61 6823.39,4266.61 v1(6832,4258) 6851.5,4258 cw(c6943.92,4165.58) 6864,4269 ccw(c6847.99,4289.72) R108.1@6872.51,4280.53
  Top Layer w7: v2(6650,4557) 6660,4557 6675,4542 6702.98,4542 6709,4535.98 R107.2@6709,4526.51 ; R109.2@6776,4526.51 6776,4536 6788,4548 6813,4548 6826,4535 6826,4479 6839,4466 6895,4466 6912,4449 6912,4416 6881,4385 v1(6881,4325)
  Top Layer w8: C250.1@5912,4511.5 v1(5912,4483) 5914.9,4480.1 U12.29@5914.9,4441.4 ; U12.28@5930.6,4441.4 5930.6,4480.6 5932,4482 v2(5932,4511.5) ; C258.1@6625,4505.5 6623,4503.5 6623,4475 6629.81,4468.19 U13.29@6629.81,4435.91 ; U13.28@6645.51,4435.91 v1(6645.51,4477.49) 6642,4481 6642,4498 C256.1@6646,4502
  Top Layer w10: R14.1@3536,5681.51 v1(3536,5693) ; R61.1@5323,4455.51 5324,4456.51 v2(5324,4491) ; v1(5711,4427) 5728.5,4427 C263.1@5729,4427.5 ; U14.L17@5885.1,5355.47 5904.77,5355.47 U14.J18@5924.46,5335.78 U14.J19@5924.46,5316.1 5924.46,5297.54 v2(5925,5297) ; U14.K19@5904.78,5316.1 5904.78,5297.22 v2(5905,5297) ; R89.2@5998,4533.51 5998,4549 v2(5999,4550) ; v2@6065,4548 6072,4541 R91.2@6072,4532.51 ; v2(6891,5229) 6862,5229 6839.32,5206.32 6839.32,5055.68 6871,5024 6913,5024 6934,5003 v2(6934,4983) v2(6946.75,4970.25) ; v1(7051,4154) 7052.62,4152.38 R124.2@7052.62,4134.97 R125.2@7073.62,4134.97
  Top Layer w20: U9.9@3965.94,5736.7 v2(4011,5736.7)
  内层2 w13: v2(5609.5,5375.16) 5656.84,5375.16 5668,5364 5668,5277 5689,5256 5738,5256 5755,5239 5841,5239 5899,5297 v2(5905,5297) 5905,5373 v2(5885,5393)
  VCC w6: 3476,5695.88 3533.12,5695.88 v1(3536,5693)
  VCC w10: 5323.62,4383 5324,4383.38 v2(5324,4491) ; 5869,4277 5886,4260 6108,4260 v2(6112,4264) ; 5931.89,4483 5932,4483.11 v2(5932,4511.5) ; v1(6832,4258) 6892,4258 6902,4248 6996,4154 v1(7051,4154)
  VCC w15: v1(5826.04,5529.95) 5826.04,5514.96 5832,5509 5877,5509 v2(5883,5515) 5905,5493 v2(5905,5297) 5905,5198.22 v1(5885.09,5178.3) 5885,5178.22 5885,5092 5894,5083 ; 5908,5079 5924,5095 5924,5296 v2(5925,5297)
  VCC w20: 3939,6165 3943,6161 3973,6131 3973,5774.7 v2(4011,5736.7) ; U15.20@5410.5,4197.4 5428,4214.9 5428,4379.05 5424.05,4383 ; 6557.3,4404 6557.3,4404.46 v1(6625.42,4472.58) 6640.59,4472.58 v1(6645.51,4477.49) 6643,4480 6643,4521.72 6650,4528.72 v2(6650,4557)
  VCC w30: v1(5711,4427) 5813.57,4427 5815.91,4429.34 ; v2(5843,4251) 5869,4277 5869,4390 5829.66,4429.34 5815.91,4429.34 ; 5897,5078 5935.63,5039.37 5935.63,4782.37 6134,4584 6134,4538.28 ; v2(5999,4550) v2(6064.35,4550) 6122.28,4550 6134,4538.28 ; 6119,4492 6134,4507 6134,4538.28 ; v1(6530,4215) 6589,4274 ; v1@6832.33,4251 6801,4251 ; v2(6934,4983) v2(6946.75,4970.25) 6991,4926 6991,4318 6921,4248 6902,4248 6801,4251 ; 5815.91,4429.34 5869.57,4483 v1(5912,4483) 5931.89,4483 6366,4483 6442,4407 v1(6442,4404) 6557.3,4404 6563.26,4404 6589,4378.26 6589,4274 ; 6589,4274 6612,4251 6801,4251
  VCC w50: 3476,5552 3476,5695.88 3476,6060 3577,6161 ; v1(3488,5547) 3484.03,5547 3410,5472.97 3410,4349 3587,4172 4388.56,4172 4630.56,4414 4865,4414 4927,4476 5174,4476 5267,4383 5323.62,4383 5424.05,4383 5667,4383 v1(5711,4427) ; H1.1@3659,6243 3577,6161 ; H1.17@4459,6243 4377,6161 3943,6161 3577,6161
  Bottom Layer w10: v2(3424,4890) 3425.78,4888.23 FPC1.4@3564.97,4888.23 ; v2(3425,4912) 3428.88,4908.12 3564.77,4908.12 FPC1.3@3564.97,4907.91 ; U15.20@5410.5,4197.4 5424,4210.9 5424,4276 ; C224.2@5411.1,4322.16 5411.1,4288.9 5424,4276 ; C223.2@5442.11,4322.1 5442.11,4294.11 5424,4276 ; RJ1.11@5733,3519.16 5791.84,3578 6194.16,3578 RJ1.14@6253,3519.16 6263.84,3530 6440.4,3530 RJ2.11@6452,3518.4 6499.6,3566 6924.4,3566 ; C174.2@5867,5375 C173.2@5867,5395 5883,5395 v2(5885,5393) ; v2(5883,5515) 5885,5517 C170.2@5885,5546 ; C169.2@5885,5161 5885.09,5161.09 v1(5885.09,5178.3) ; C175.2@5904,5276 5904,5296 v2(5905,5297) 5904.22,5297.78 C167.2@5904.22,5320.22 ; C168.2@5919.22,5306.22 5925,5300.44 v2(5925,5297) C176.2@5925,5276 ; C276.1@6881,5449.5 6859.26,5449.5 U16.5@6840.91,5431.15 6840.91,5422.09 6909,5354 6909,5244 6894,5229 v2(6891,5229) ; RJ2.14@6972,3518.4 6924.4,3566 ; v2(6999,4635) 7023,4635 ; v1(7051,4154) 7089,4116 ; FPC2.2@7072.02,4600.26 7005.74,4600.26 6997,4609 7007.94,4619.94 ; FPC2.3@7072.02,4619.94 7007.94,4619.94 ; FPC2.4@7072.02,4639.62 7027.62,4639.62 7023,4635 ; U11.5@7239,4181.39 C204.2@7239,4126.5 7229.5,4126.5 7219,4116 7089,4116 ; 6924.4,3566 6952,3566 7102,3716 7102,4103 7089,4116 ; 7007.94,4619.94 7023,4635
  Bottom Layer w13: C178.2@5607.38,5374.75 5607.63,5375 C177.2@5630,5375
  Bottom Layer w15: v1(6645.51,4477.49) 6646,4477 6734,4477 6745,4488 6771,4488 6784,4475 6784,4427 6813,4398 6868,4398 6887,4379 6887,4331 v1(6881,4325)
  Bottom Layer w25: v2(6064.35,4550) 6065.35,4551 6097,4551 ; 6101,4550 6126,4525 6126,4489 6071,4434 6071,4346 6095,4322 v1@6179.07,4322
  other v1: 3510,5548 3529,5567 3488,5568 3509,5568
  other v2: 6999.28,4611.28
GM1_INTB: R106.2 U13.31 | length 90.3
  Top Layer w4: R106.2@6503.51,4426 6546,4426 6563.59,4408.41 U13.31@6586.51,4408.41
GM1_LED0: R110.1 U13.32 | length 88.1
  Top Layer w4: R110.1@6503.51,4405 6504,4404.51 6545.49,4404.51 6557.39,4392.61 U13.32@6586.51,4392.61
GM1_LED1: R98.2 R112.2 U13.33 | length 1011.5
  Top Layer w4: v2(6553.09,4376.91) U13.33@6586.51,4376.91
  Top Layer w6: v1(6352,3779) 6377,3754 6377,3721 6365.61,3709.61 R112.2@6362.37,3709.61 R98.2@6362.37,3687.63
  内层2 w6: v1(6352,3779) 6338,3765 6288,3765 6239,3814 6239,3867.95 6274.05,3903 6329,3903 6368,3942 6368,4187 6528,4347 6535,4347 6553.09,4365.09 v2(6553.09,4376.91)
GM1_LED2: R97.1 R114.2 U13.34 | length 972.2
  Top Layer w4: v2(6529.98,4367) 6542,4367 6547.89,4361.11 U13.34@6586.51,4361.11
  Top Layer w6: v1(6326,3748) 6322,3744 6322,3716 6328.39,3709.61 R114.2@6338.37,3709.61 R97.1@6338.37,3687.63
  内层2 w6: v1(6326,3748) 6322,3752 6282,3752 6228,3806 6228,3875 6271,3918 6323,3918 6354,3949 6354,4191.02 v2(6529.98,4367)
GM1_MDIN0: RJ2.P3 U13.2 | length 340.9
  Top Layer w5: RJ2.P3@6586.8,4063.4 6594,4056.2 6594,4026 6587,4019 6562,4019 6541,4040 6541,4107.25 6626.41,4192.66 6626.41,4217.47 6629.81,4220.86 U13.2@6629.81,4239.11
GM1_MDIN1: RJ2.P7 U13.5 | length 556
  Top Layer w5: 6674.66,4136.33 6672.02,4133.69 ; U13.5@6677.01,4239.11 6676.43,4238.54 6676.43,4138.09 6672.02,4133.69 ; RJ2.P7@6786.8,4063.4 6772.4,4049 6772.4,3940.81 6755.4,3923.81 6714.4,3923.81 6688.42,3949.8 6688.42,3992.8 6643.4,4037.81 6643.4,4105.06 6672.02,4133.69
GM1_MDIN2: RJ2.P6 U13.7 | length 306
  Top Layer w5: U13.7@6708.51,4239.11 6708.51,4218.34 6706.16,4216 6706.16,4137.56 6741.02,4102.71 6741.02,4037.27 6719,4015.25 6719,3977.3 RJ2.P6@6732.9,3963.4
GM1_MDIN3: RJ2.P9 U13.10 | length 334.5
  Top Layer w5: U13.10@6755.81,4239.11 6755.81,4220.86 6752.41,4217.47 6752.41,4189.59 6841.02,4100.98 6841.02,4039.98 6863,4018 6880,4018 6888,4026 6888,4062.2 RJ2.P9@6886.8,4063.4
GM1_MDIP0: RJ2.P2 U13.1 | length 334.8
  Top Layer w5: RJ2.P2@6532.9,3963.4 6533.4,3963.4 6559,3989 6559,4009.25 6531.98,4036.27 6531.98,4110.98 6617.4,4196.4 6617.4,4217.47 6614.01,4220.86 U13.1@6614.01,4239.11
GM1_MDIP1: RJ2.P4 U13.4 | length 555.7
  Top Layer w5: RJ2.P4@6632.9,3963.4 6632.9,3894.31 6652.4,3874.81 6689.4,3874.81 6708.4,3893.81 6708.4,3915.81 6679.4,3944.81 6679.4,3989.06 6634.38,4034.08 6634.38,4108.8 6667.42,4141.83 6667.42,4215 6661.31,4221.11 U13.4@6661.31,4239.11 ; RJ2.P4@6634.3,3965.97 RJ2.P4@6636.4,3963.87
GM1_MDIP2: RJ2.P5 U13.6 | length 302.6
  Top Layer w5: RJ2.P5@6686.8,4063.4 6685,4061.6 6685,4037 6700,4022 6713,4022 6732,4041 6732,4099 6697.15,4133.85 6697.15,4216 6692.81,4220.34 U13.6@6692.81,4239.11
GM1_MDIP3: RJ2.P8 U13.9 | length 337.3
  Top Layer w5: U13.9@6740.01,4239.11 6740.01,4220.86 6743.4,4217.47 6743.4,4185.85 6832,4097.25 6832,4036.25 6859,4009.25 6859,3987 6835.4,3963.4 RJ2.P8@6832.9,3963.4
GM1_REGOUT: L10.1 U13.30
GM1_RSET: R103.2 U13.39 | length 123.4
  Top Layer w4: R103.2@6500.51,4219 6508,4219 6520,4231 6535.09,4231 6555,4250.91 6555,4270 6567.41,4282.41 U13.39@6586.51,4282.41
GM1_XTAL_IN: C259.2 U13.36 X4.1 | length 154.7
  Top Layer w4: C259.2@6527,4319 6534,4312 6546,4312 6563.61,4329.61 U13.36@6586.51,4329.61
  Top Layer w6: X4.1@6459,4332 6486,4305 6513,4305 C259.2@6527,4319
GM1_XTAL_OUT: C257.2 U13.37 X4.3 | length 110.1
  Top Layer w4: C257.2@6527,4285 6527,4294 6534,4301 6552,4301 6564.91,4313.91 U13.37@6586.51,4313.91
  Top Layer w6: X4.3@6499,4272 6512,4285 C257.2@6527,4285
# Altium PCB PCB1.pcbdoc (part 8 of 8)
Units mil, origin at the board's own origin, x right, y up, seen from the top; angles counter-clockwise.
Board outline 5129 x 4161 mil, 8 copper layers (Top Layer, GND1, 内层2, VCC, 内层4, Inner5, GND2, Bottom Layer); 495 components, 453 nets, 2562 pads, 1123 vias.

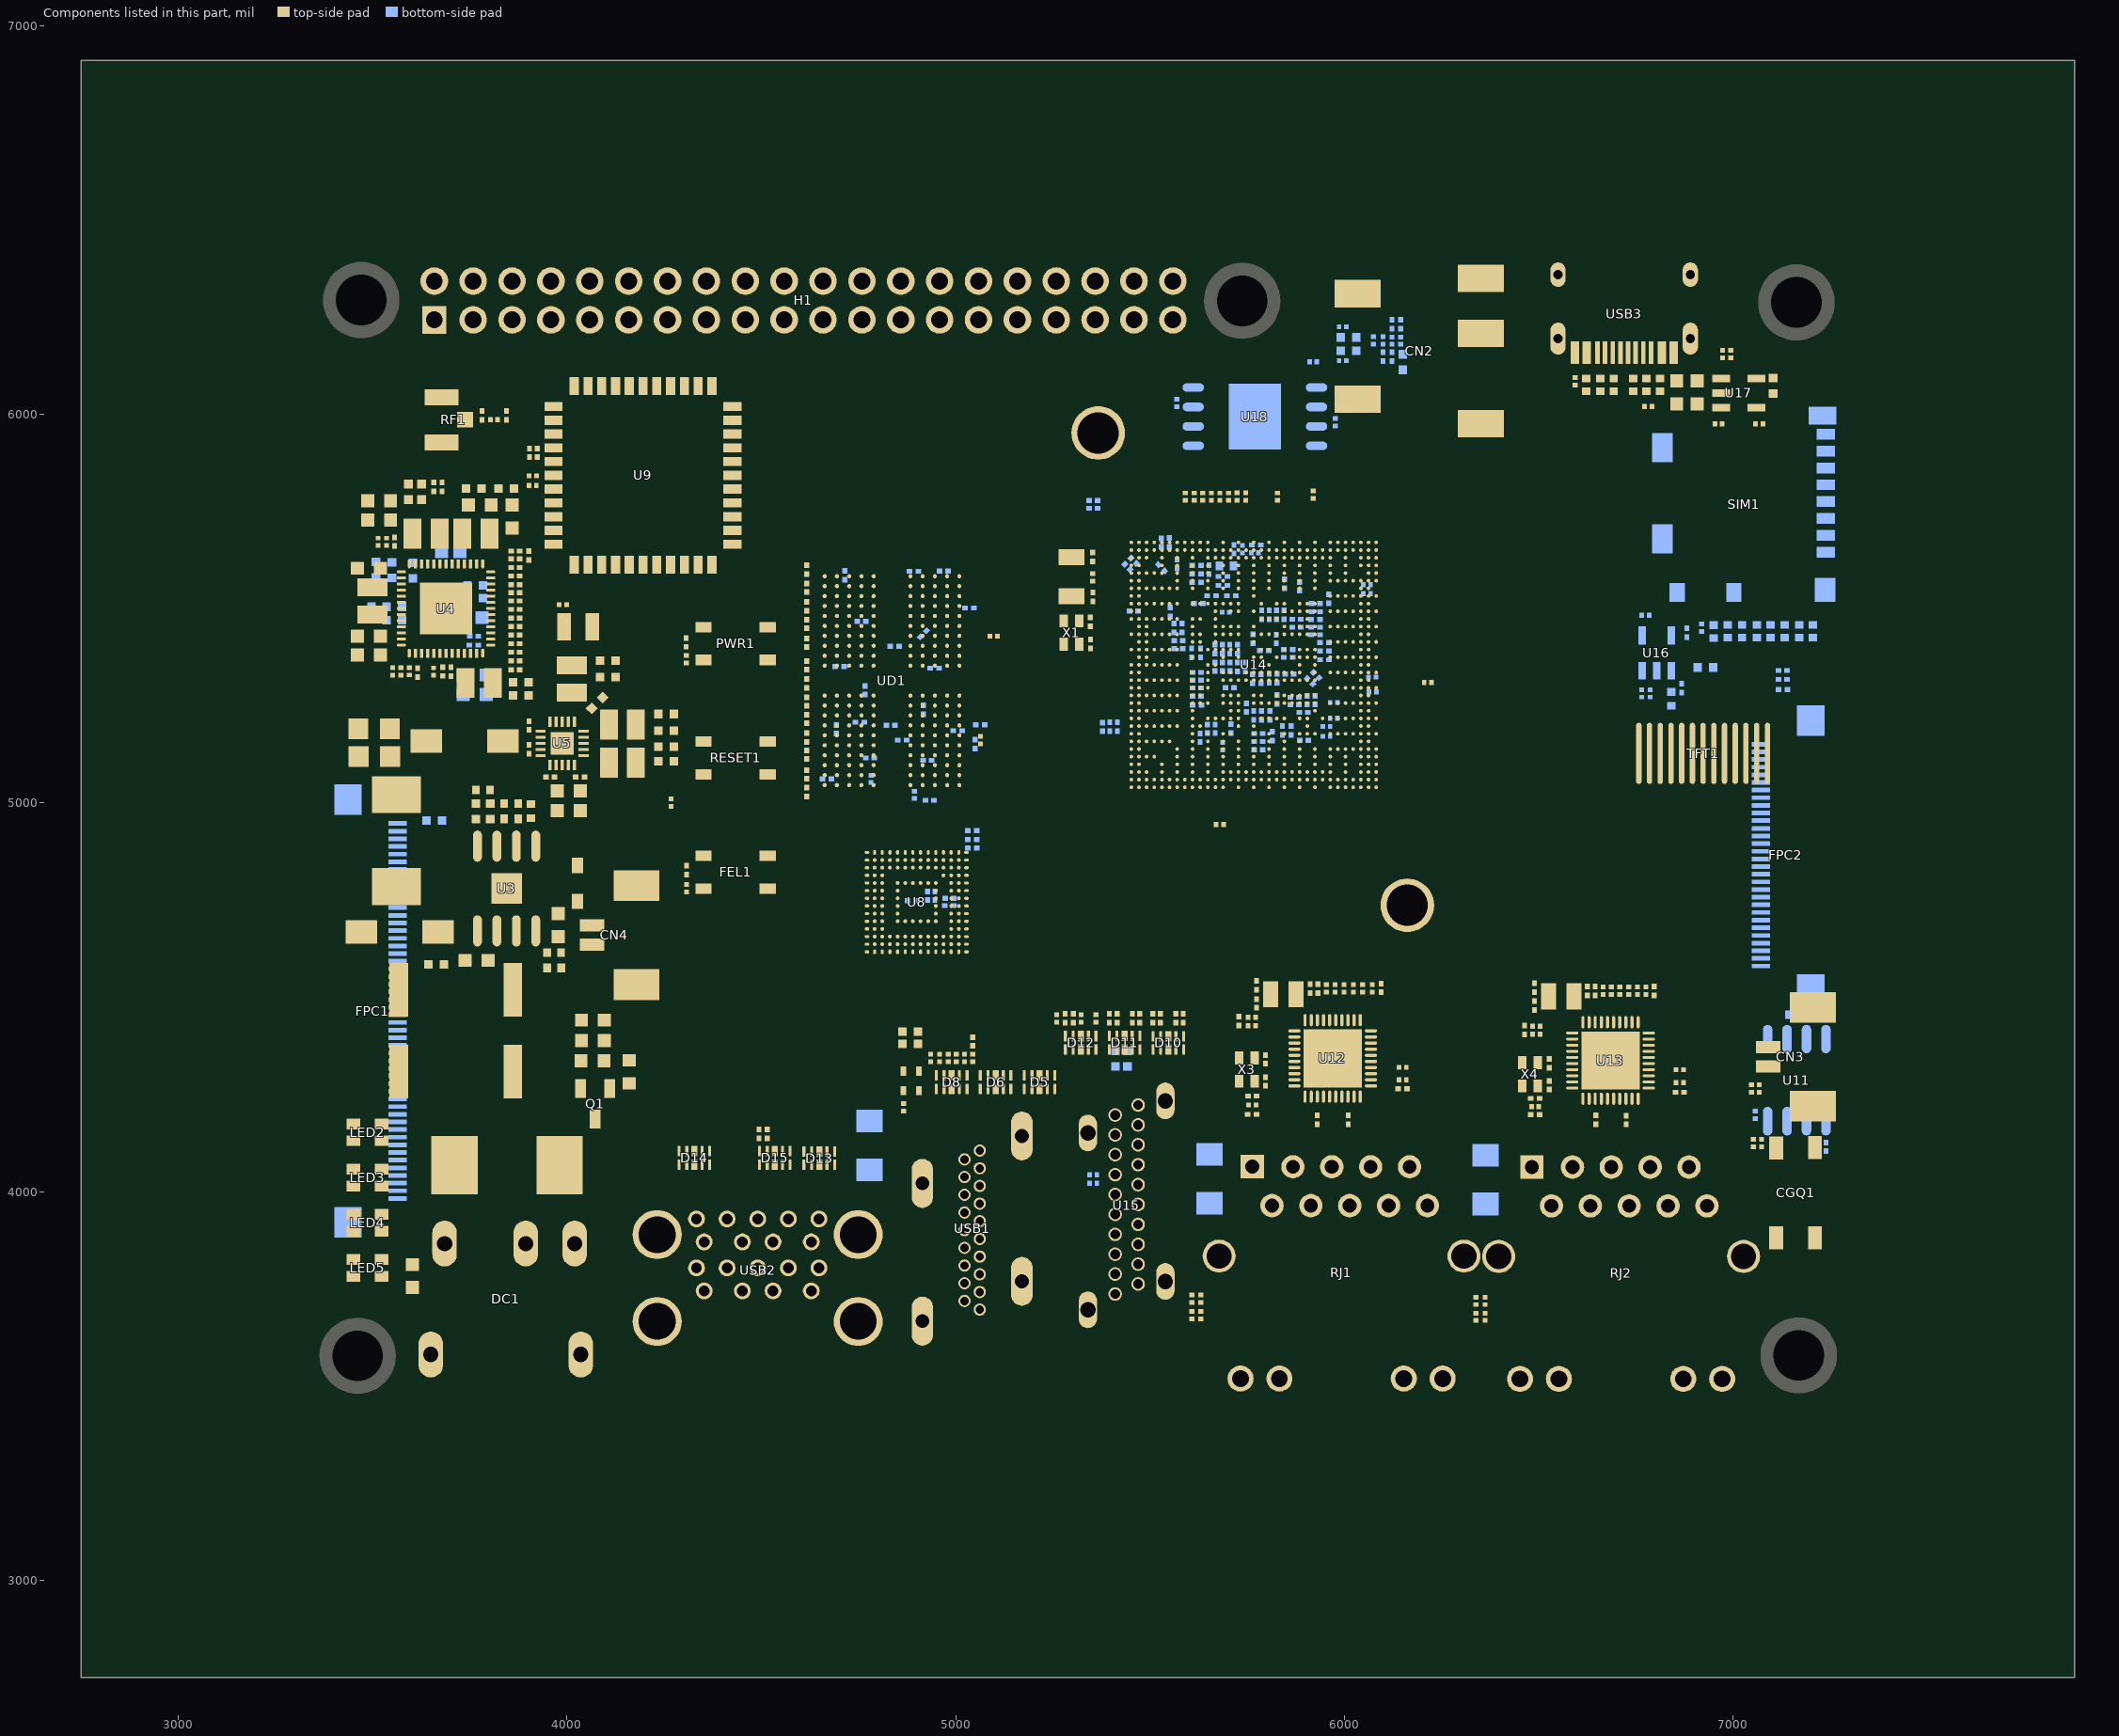
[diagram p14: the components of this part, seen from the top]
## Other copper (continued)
VCC:
  region net GM1_DVDDRG: 3536.68,5559.03 3493.65,5516 3474,5516 3454,5536 3454,5558.59 3490.41,5595 3522.93,5595 3536.68,5581.24
  region net GM1_DVDDRG: 3574.97,6194.32 3605.89,6154.53 ccw(c3552.51,6207.92) 3628,6207.57 3628,6278.43 cw(c3415.9,6353.39)
  region net GM1_DVDDRG: 4407.21,6226.57 4442.57,6191.21 4443.99,6192.73 4445.23,6194.22 4446.58,6196.05 4449.42,6200.43 4450.43,6201.92 4451.27,6203.02 4451.94,6203.79 4452.42,6204.27 4452.91,6204.72 4453.44,6205.15 4454,6205.54 4454.6,6205.91 4455.24,6206.25 4455.93,6206.55 4456.66,6206.82 4457.45,6207.06 4458.3,6207.26 4459.21,6207.42 4460.69,6207.6 4461.22,6207.64 4423.64,6245.22 4423.49,6243.68 4423.35,6242.74 4423.16,6241.87 4422.94,6241.05 4422.69,6240.29 4422.4,6239.58 4422.08,6238.92 4421.73,6238.3 4421.35,6237.72 4420.94,6237.17 4420.5,6236.66 4420.03,6236.18 4419.29,6235.49 4418.48,6234.85 4417.04,6233.82 4412.76,6231.07 4410.96,6229.8 4409.48,6228.63 4407.97,6227.3
  region net PE6: 4590.7,6206.48 4593.52,6209.3 4592.92,6209.99 4592.4,6210.74 4591.96,6211.56 4591.59,6212.44 4591.3,6213.37 4591.08,6214.36 4590.91,6215.39 4590.81,6216.47 4590.77,6218.74 4590.9,6221.13 4591.36,6224.9 4593.52,6236.45 4594.08,6240.02 4594.32,6242.23 4594.4,6244.27 4594.36,6245.22 4556.78,6207.64 4558.53,6207.6 4561.54,6207.76 4573.45,6209.06 4578.36,6209.39 4580.71,6209.41 4582.95,6209.3 4585.04,6209.04 4586.02,6208.83 4586.95,6208.58 4587.82,6208.28 4588.64,6207.92 4589.39,6207.5 4590.08,6207.02
  region net PE1: 4692.2,6207.98 4695.02,6210.8 4694.46,6211.44 4693.97,6212.14 4693.55,6212.91 4693.19,6213.74 4692.89,6214.63 4692.64,6215.58 4692.45,6216.57 4692.21,6218.68 4692.14,6220.95 4692.29,6224.54 4692.97,6230.8 4694.2,6240.35 4694.39,6243.42 4694.36,6245.22 4656.78,6207.64 4658.68,6207.62 4660.76,6207.76 4665.39,6208.39 4676.8,6210.29 4680.54,6210.68 4682.91,6210.77 4685.15,6210.69 4686.22,6210.57 4687.24,6210.4 4688.21,6210.17 4689.13,6209.88 4689.99,6209.51 4690.79,6209.08 4691.53,6208.57
  region net PE5: 4624.98,6308.8 4627.8,6305.98 4628.4,6306.51 4629.07,6306.98 4629.81,6307.39 4630.61,6307.75 4631.48,6308.05 4632.39,6308.31 4633.35,6308.52 4635.42,6308.82 4637.63,6308.97 4641.15,6308.97 4647.28,6308.57 4657.6,6307.66 4660.39,6307.6 4661.22,6307.64 4623.64,6345.22 4623.6,6344.25 4623.69,6342.16 4623.95,6339.91 4624.84,6335.03 4626.98,6324.61 4627.52,6320.81 4627.7,6318.38 4627.69,6316.09 4627.6,6315 4627.45,6313.95 4627.23,6312.95 4626.94,6312 4626.57,6311.11 4626.13,6310.28 4625.6,6309.51
  region net PE8: 4782.7,6198.48 4785.52,6201.3 4785.08,6201.78 4784.68,6202.27 4784.31,6202.77 4783.99,6203.28 4783.71,6203.81 4783.46,6204.36 4783.25,6204.91 4783.08,6205.48 4782.94,6206.05 4782.83,6206.64 4782.76,6207.24 4782.7,6208.47 4782.76,6209.74 4782.92,6211.05 4783.17,6212.39 4783.72,6214.46 4784.43,6216.58 4785.88,6220.23 4790.7,6230.81 4792.24,6234.57 4793.02,6236.8 4793.66,6238.98 4793.98,6240.41 4794.22,6241.82 4794.36,6243.2 4794.39,6244.56 4794.36,6245.22 4756.78,6207.64 4761.07,6207.24 4764.59,6206.71 4768.12,6205.95 4770.72,6205.22 4773.25,6204.34 4774.88,6203.66 4776.46,6202.91 4777.98,6202.07 4779.44,6201.15 4780.81,6200.15 4782.09,6199.06
  region net PE7: 4722.98,6310.8 4725.8,6307.98 4726.47,6308.57 4727.21,6309.08 4728.01,6309.51 4728.87,6309.88 4729.79,6310.17 4730.76,6310.4 4731.78,6310.57 4732.85,6310.69 4735.09,6310.77 4737.46,6310.68 4741.2,6310.29 4752.61,6308.39 4757.24,6307.76 4759.32,6307.62 4761.22,6307.64 4723.64,6345.22 4723.61,6343.42 4723.8,6340.35 4725.19,6329.54 4725.71,6324.54 4725.86,6320.95 4725.79,6318.68 4725.55,6316.57 4725.36,6315.58 4725.11,6314.63 4724.81,6313.74 4724.45,6312.91 4724.03,6312.14 4723.54,6311.44
  region net PE12: 4823.48,6310.3 4826.3,6307.48 4826.96,6308.05 4827.68,6308.55 4828.46,6308.98 4829.31,6309.34 4830.21,6309.64 4831.17,6309.88 4832.18,6310.06 4834.32,6310.27 4836.6,6310.3 4840.24,6310.08 4846.56,6309.26 4856.24,6307.84 4858.37,6307.66 4860.32,6307.6 4861.22,6307.64 4823.64,6345.22 4823.61,6343.37 4823.73,6341.33 4824.29,6336.78 4825.95,6325.49 4826.26,6321.79 4826.31,6319.44 4826.19,6317.23 4826.06,6316.18 4825.88,6315.17 4825.64,6314.21 4825.34,6313.31 4824.98,6312.46 4824.55,6311.68 4824.05,6310.96
  region net GM1_DVDDRG: 5434.42,4207.18 5420.28,4221.32 5417.89,4219.05 5416.63,4218 5415.31,4217.04 5413.94,4216.22 5413.23,4215.86 5412.5,4215.56 5411.76,4215.3 5410.99,4215.09 5410.21,4214.95 5409.4,4214.87 5427.97,4196.3 5428.05,4197.11 5428.19,4197.89 5428.4,4198.66 5428.66,4199.4 5428.96,4200.13 5429.32,4200.84 5430.14,4202.21 5431.1,4203.53 5432.15,4204.79
  region net ALDO3: 3561.47,5320.46 3557.23,5324.7 3556.61,5324.18 3555.95,5323.78 3555.24,5323.47 3554.49,5323.25 3553.71,5323.09 3552.1,5322.91 3551.27,5322.86 3559.63,5314.51 3559.75,5316.14 3559.86,5316.94 3560.02,5317.72 3560.24,5318.47 3560.55,5319.18 3560.95,5319.85
  region net USB0-DP: 6332.5,5223.37 6327.5,5223.37 6327.42,5222.49 6327.21,5221.75 6326.87,5221.12 6326.44,5220.55 6325.35,5219.47 6324.09,5218.21 6335.91,5218.21 6334.65,5219.47 6333.56,5220.55 6333.13,5221.12 6332.79,5221.75 6332.58,5222.49
  region net USB0-DM: 6312.5,5220.72 6307.5,5220.72 6307.42,5219.82 6307.21,5219.04 6306.87,5218.35 6306.44,5217.72 6305.92,5217.12 6304.09,5215.21 6315.91,5215.21 6314.08,5217.12 6313.56,5217.72 6313.13,5218.35 6312.79,5219.04 6312.58,5219.82
  region net GM1_DVDDRG: 6842.72,4253 6842.72,4263 6840.43,4262.9 6839.75,4262.9 6839.1,4262.97 6838.46,4263.14 6837.84,4263.44 6837.21,4263.91 6837.21,4252.09 6837.84,4252.56 6838.46,4252.86 6839.1,4253.03 6839.75,4253.1 6840.43,4253.1
  region net FEL: 5972.8,5398.16 5972.8,5392.16 5973.6,5392.1 5974.35,5391.91 5975.07,5391.63 5975.76,5391.25 5976.42,5390.81 5977.69,5389.8 5978.31,5389.26 5978.31,5401.07 5977.06,5400 5976.42,5399.51 5975.76,5399.07 5975.07,5398.7 5974.35,5398.41 5973.6,5398.23
  region net PE12: 6087.01,5761.83 6089.83,5759.01 6090.6,5759.65 6091.34,5760.04 6092.08,5760.23 6092.84,5760.29 6094.5,5760.18 6095.45,5760.13 6096.49,5760.14 6088.14,5768.49 6088.13,5767.45 6088.25,5765.64 6088.29,5764.84 6088.27,5764.46 6088.23,5764.08 6088.16,5763.71 6088.04,5763.34 6087.87,5762.97 6087.65,5762.6 6087.36,5762.22
  region net PE8: 6176.01,5760.83 6178.83,5758.01 6179.6,5758.65 6180.34,5759.04 6181.08,5759.23 6181.84,5759.29 6183.5,5759.18 6184.45,5759.13 6185.49,5759.14 6177.14,5767.49 6177.13,5766.45 6177.25,5764.64 6177.29,5763.84 6177.27,5763.46 6177.23,5763.08 6177.16,5762.71 6177.04,5762.34 6176.87,5761.97 6176.65,5761.6 6176.36,5761.22
  region net PE7: 6205,5757.28 6209,5757.28 6209.09,5758.27 6209.34,5759.08 6209.72,5759.74 6210.22,5760.31 6211.47,5761.41 6212.18,5762.04 6212.91,5762.79 6201.09,5762.79 6201.82,5762.04 6203.19,5760.85 6203.78,5760.31 6204.04,5760.03 6204.28,5759.74 6204.49,5759.42 6204.66,5759.08 6204.81,5758.7 6204.91,5758.27 6204.98,5757.8
  region net PE5: 6155.28,5712 6155.28,5708 6155.95,5707.96 6156.67,5707.86 6157.43,5707.69 6158.19,5707.46 6158.94,5707.18 6159.64,5706.86 6160.26,5706.49 6160.79,5706.09 6160.79,5717.91 6160.17,5717.23 6158.9,5715.39 6158.25,5714.4 6157.56,5713.48 6156.85,5712.72 6156.09,5712.19
  region net PE6: 6180.01,5704.83 6182.83,5702.01 6183.38,5702.47 6184.02,5702.88 6184.71,5703.24 6185.46,5703.53 6186.23,5703.77 6187,5703.95 6187.76,5704.07 6188.49,5704.14 6180.14,5712.49 6180.16,5711.65 6180.56,5708.44 6180.64,5707.35 6180.61,5706.35 6180.41,5705.49
  region net PE1: 6202.83,5720.99 6200.01,5718.17 6200.65,5717.4 6201.04,5716.66 6201.23,5715.92 6201.29,5715.16 6201.18,5713.5 6201.13,5712.55 6201.14,5711.51 6209.49,5719.86 6208.45,5719.87 6206.64,5719.75 6205.84,5719.71 6205.46,5719.73 6205.08,5719.77 6204.71,5719.84 6204.34,5719.96 6203.97,5720.13 6203.6,5720.35 6203.22,5720.64
  region net CLDO3: 7143.12,5497.44 7136.04,5504.52 7134.5,5502.83 7134.02,5502.35 7133.51,5501.93 7132.94,5501.6 7132.28,5501.37 7131.51,5501.26 7139.86,5492.91 7139.97,5493.68 7140.2,5494.34 7140.53,5494.91 7140.95,5495.42 7141.43,5495.9
  region net GM1_DVDDRG: 7040.28,4159 7040.28,4149 7042.57,4149.1 7043.25,4149.1 7043.9,4149.03 7044.54,4148.86 7045.16,4148.56 7045.79,4148.09 7045.79,4159.91 7045.16,4159.44 7044.54,4159.14 7043.9,4158.97 7043.25,4158.9 7042.57,4158.9
  region net GM1_DVDDRG: 3525.28,5698.88 3525.28,5692.88 3526.08,5692.69 3526.83,5692.18 3527.55,5691.43 3528.24,5690.53 3530.17,5687.76 3530.79,5687.09 3530.79,5698.91 3530.08,5698.38 3529.45,5698.14 3528.87,5698.1 3528.29,5698.21 3527.01,5698.63 3526.22,5698.81
  region net AP-RESET: 3985,5064.28 3991,5064.28 3991.07,5065.08 3991.25,5065.84 3991.54,5066.55 3991.91,5067.24 3992.35,5067.9 3993.36,5069.17 3993.91,5069.79 3982.09,5069.79 3983.16,5068.54 3983.65,5067.9 3984.09,5067.24 3984.46,5066.55 3984.75,5065.84 3984.93,5065.08
  region net USB0-DP: 6723.23,6014.77 6726.77,6011.23 6727.43,6011.79 6728.07,6012.12 6728.7,6012.28 6729.35,6012.31 6730.77,6012.19 6731.58,6012.13 6732.49,6012.14 6724.14,6020.49 6724.13,6019.58 6724.26,6018.03 6724.31,6017.35 6724.28,6016.7 6724.12,6016.07 6723.79,6015.43
  region net USB0-DM: 6714.23,6011.23 6717.77,6014.77 6717.21,6015.43 6716.88,6016.07 6716.72,6016.7 6716.69,6017.35 6716.81,6018.77 6716.87,6019.58 6716.86,6020.49 6708.51,6012.14 6709.42,6012.13 6710.97,6012.26 6711.65,6012.31 6712.3,6012.28 6712.93,6012.12 6713.57,6011.79
  region net GM1_DVDDRG: 5319,4480.31 5329,4480.31 5328.89,4482.59 5328.89,4483.27 5328.95,4483.92 5329.12,4484.55 5329.42,4485.18 5329.89,4485.81 5318.11,4485.81 5318.58,4485.18 5318.88,4484.55 5319.05,4483.92 5319.11,4483.27 5319.11,4482.59
  region net VDD-DNRFB: 5657.46,5430.19 5664.53,5423.12 5666.06,5424.81 5666.54,5425.29 5667.05,5425.7 5667.62,5426.03 5668.27,5426.26 5669.04,5426.38 5660.72,5434.7 5660.6,5433.93 5660.37,5433.28 5660.04,5432.71 5659.63,5432.2 5659.15,5431.73
  region net VDD-DNRFB: 3963.09,5272.02 3956.02,5279.09 3954.49,5277.4 3954.01,5276.92 3953.5,5276.51 3952.94,5276.18 3952.28,5275.95 3951.51,5275.83 3959.83,5267.51 3959.95,5268.28 3960.18,5268.94 3960.51,5269.5 3960.92,5270.01 3961.4,5270.49
  region net CLDO3: 5592.69,6055.13 5585.62,6062.2 5584.08,6060.51 5583.6,6060.02 5583.1,6059.61 5582.53,6059.28 5581.87,6059.05 5581.1,6058.94 5589.43,6050.61 5589.54,6051.38 5589.77,6052.04 5590.1,6052.61 5590.51,6053.11 5590.99,6053.59
  region net AP-RESET: 3614.5,5402.31 3619.5,5402.31 3619.53,5402.89 3619.6,5403.4 3619.72,5403.84 3619.88,5404.22 3620.08,5404.56 3620.31,5404.85 3620.58,5405.12 3620.87,5405.37 3621.9,5406.1 3622.67,5406.66 3623.07,5406.99 3623.48,5407.37 3623.89,5407.81 3612.11,5407.81 3612.56,5407.26 3612.99,5406.63 3613.39,5405.95 3613.75,5405.23 3614.06,5404.49 3614.29,5403.74 3614.45,5403.01
  region net AP-NMI: 3636,5401.31 3642,5401.31 3642.16,5402.02 3642.59,5402.76 3643.22,5403.5 3643.99,5404.23 3646.33,5406.25 3646.89,5406.81 3635.11,5406.81 3635.58,5406.18 3635.88,5405.55 3636.05,5404.92 3636.11,5404.27 3636.11,5403.59
  region net AP-NMI: 3634.86,5420.97 3632.03,5418.14 3632.67,5417.38 3633.06,5416.64 3633.25,5415.9 3633.31,5415.15 3633.2,5413.49 3633.15,5412.55 3633.17,5411.51 3641.49,5419.83 3640.45,5419.85 3638.65,5419.73 3637.85,5419.69 3637.47,5419.71 3637.1,5419.75 3636.73,5419.82 3636.36,5419.94 3635.99,5420.11 3635.62,5420.33 3635.24,5420.62
  region net AP-NMI: 3637.03,5582.86 3639.86,5580.03 3640.62,5580.67 3641.36,5581.06 3642.1,5581.25 3642.85,5581.31 3644.51,5581.2 3645.45,5581.15 3646.49,5581.17 3638.17,5589.49 3638.15,5588.45 3638.27,5586.65 3638.31,5585.85 3638.29,5585.47 3638.25,5585.1 3638.18,5584.73 3638.06,5584.36 3637.89,5583.99 3637.67,5583.62 3637.38,5583.24
  region net ALDO3: 3851.06,5419.68 3846.82,5415.44 3847.34,5414.83 3847.74,5414.16 3848.05,5413.46 3848.27,5412.71 3848.43,5411.93 3848.61,5410.33 3848.67,5409.51 3856.99,5417.83 3855.36,5417.96 3854.57,5418.07 3853.79,5418.23 3853.04,5418.45 3852.34,5418.76 3851.67,5419.16
  region net AP-RESET: 3912.31,5202.5 3912.31,5197.5 3912.95,5197.57 3913.66,5197.74 3915.21,5198.19 3915.97,5198.37 3916.68,5198.45 3917.3,5198.38 3917.81,5198.11 3917.81,5209.89 3917.43,5209.5 3917.08,5209.04 3916.76,5208.52 3916.17,5207.36 3915.03,5204.91 3914.73,5204.35 3914.4,5203.84 3914.05,5203.39 3913.68,5203.02 3913.26,5202.74 3912.81,5202.56
  region net FEL: 4109.69,5789 4109.69,5795 4108.89,5795.06 4108.14,5795.25 4107.42,5795.53 4106.74,5795.9 4106.07,5796.34 4104.81,5797.35 4104.19,5797.89 4104.19,5786.11 4105.43,5787.17 4106.07,5787.66 4106.74,5788.1 4107.42,5788.47 4108.14,5788.75 4108.89,5788.94
  region net AP-NMI: 3642,5360.69 3636,5360.69 3635.94,5359.89 3635.75,5359.14 3635.47,5358.42 3635.1,5357.74 3634.66,5357.07 3633.65,5355.81 3633.11,5355.19 3644.89,5355.19 3643.83,5356.43 3643.34,5357.07 3642.9,5357.74 3642.53,5358.42 3642.25,5359.14 3642.06,5359.89
  region net CPUX-RX: 6797.2,6104.12 6801.2,6104.12 6801.28,6105.11 6801.53,6105.9 6801.91,6106.56 6802.41,6107.14 6803.66,6108.24 6804.36,6108.86 6805.08,6109.61 6793.31,6109.61 6794.03,6108.86 6795.39,6107.68 6795.98,6107.14 6796.24,6106.86 6796.48,6106.56 6796.69,6106.25 6796.86,6105.9 6797,6105.53 6797.11,6105.11 6797.17,6104.64
  region net CPUX-TX: 6660.1,6113.36 6660.1,6109.36 6661.09,6109.28 6661.89,6109.03 6662.55,6108.65 6663.13,6108.15 6664.22,6106.9 6664.85,6106.2 6665.6,6105.48 6665.6,6117.25 6664.85,6116.53 6663.67,6115.17 6663.13,6114.58 6662.85,6114.32 6662.55,6114.08 6662.24,6113.87 6661.89,6113.7 6661.51,6113.56 6661.09,6113.45 6660.62,6113.39
  region net CPUX-RX: 6300,5262.69 6296,5262.69 6295.91,5261.7 6295.67,5260.9 6295.28,5260.24 6294.79,5259.66 6293.54,5258.57 6292.84,5257.94 6292.11,5257.19 6303.89,5257.19 6303.16,5257.94 6301.8,5259.12 6301.21,5259.66 6300.95,5259.94 6300.72,5260.24 6300.51,5260.55 6300.33,5260.9 6300.19,5261.28 6300.09,5261.7 6300.02,5262.17
  region net CPUX-TX: 6286.97,5269.14 6284.14,5271.97 6283.38,5271.33 6282.64,5270.94 6281.9,5270.75 6281.15,5270.69 6279.49,5270.8 6278.55,5270.85 6277.51,5270.83 6285.83,5262.51 6285.85,5263.55 6285.73,5265.35 6285.69,5266.15 6285.71,5266.53 6285.75,5266.9 6285.82,5267.27 6285.94,5267.64 6286.11,5268.01 6286.33,5268.38 6286.62,5268.76
  region net GM1_DVDDRG: 6101.31,4265 6101.31,4255 6102.13,4255.19 6102.89,4255.7 6103.6,4256.38 6104.92,4257.78 6105.55,4258.26 6106.18,4258.41 6106.81,4258.11 6106.81,4269.89 6106.25,4269.33 6104.23,4266.99 6103.5,4266.22 6102.76,4265.59 6102.02,4265.16
  region net CLDO2: 5785,5099.31 5795,5099.31 5794.89,5101.59 5794.89,5102.27 5794.95,5102.92 5795.12,5103.55 5795.42,5104.18 5795.89,5104.81 5784.11,5104.81 5784.58,5104.18 5784.88,5103.55 5785.05,5102.92 5785.11,5102.27 5785.11,5101.59
  region net CLDO2: 3861.5,5594.69 3851.5,5594.69 3851.61,5592.41 3851.61,5591.73 3851.55,5591.08 3851.38,5590.45 3851.08,5589.82 3850.61,5589.19 3862.39,5589.19 3861.92,5589.82 3861.62,5590.45 3861.45,5591.08 3861.39,5591.73 3861.39,5592.41
  region net AP-RESET: 4234.31,4994 4234.31,4988 4235.11,4987.94 4235.86,4987.75 4236.58,4987.47 4237.26,4987.1 4237.93,4986.66 4239.19,4985.65 4239.81,4985.11 4239.81,4996.89 4238.57,4995.83 4237.93,4995.34 4237.26,4994.9 4236.58,4994.53 4235.86,4994.25 4235.11,4994.06
  region net GM1_DVDDRG: 5927,4500.81 5937,4500.81 5936.89,4503.09 5936.89,4503.77 5936.95,4504.42 5937.12,4505.05 5937.42,4505.68 5937.89,4506.31 5926.11,4506.31 5926.58,4505.68 5926.88,4505.05 5927.05,4504.42 5927.11,4503.77 5927.11,4503.09
  region net GM1_DVDDRG: 6430,4440.21 6406.24,4421.54 ccw(c6457.92,4473.22) 6427.28,4406.87 6444.85,4419 ccw(c6377.32,4387.53)
  region net GM1_DVDDRG: 6567.79,4231.57 6571.84,4235.43 6574.97,4238.09 6577.61,4240.09 6579.75,4241.5 6581.36,4242.43 6582.97,4243.25 6584.59,4243.94 6585.67,4244.32 6586.75,4244.64 6587.82,4244.88 6588.9,4245.06 6589.97,4245.16 6591.04,4245.18 6592.1,4245.13 6593.16,4244.98 6594.21,4244.75 6595.26,4244.43 6596.3,4244.01 6597.34,4243.49 6598.37,4242.88 6599.38,4242.16 6600.39,4241.33 6601.39,4240.39 6622.61,4261.61 6620.74,4263.6 6618.98,4265.73 6617.33,4267.98 6615.8,4270.33 6613.91,4273.63 6612.21,4277.09 6610.69,4280.68 6609.03,4285.32 6607.63,4290.1 6606.27,4295.93 6605.25,4301.82 6604.54,4307.68 6604.09,4314.37 6604,4319 6574,4319 6573.91,4316.19 6573.65,4313.21 6573.05,4309.03 6571.92,4303.53 6570.4,4297.81 6568.13,4290.79 6565.43,4283.76 6562.37,4276.88 6559.01,4270.31 6556.04,4265.2 6552.95,4260.51 6550.42,4257.13 6548.5,4254.84 6546.57,4252.79
  region net GM1_DVDDRG: 6845.53,4234.67 6846.43,4264.66 6815.99,4250.55 6756,4266
  region net GM1_DVDDRG: 6866.57,4234.05 6871.3,4233.78 6876.8,4233.17 6883.08,4232.14 6889.51,4230.74 6896.58,4228.81 6903.02,4226.69 6909.31,4224.24 6914.83,4221.74 6919.57,4219.27 6923.57,4216.92 6926.87,4214.73 6929.95,4212.44 6932.41,4210.38 6934.31,4208.61 6934.68,4208.25 6941.75,4215.32 6940.72,4216.25 6937.66,4218.59 6925.42,4227.24 6922.87,4229.2 6921.52,4230.35 6920.98,4230.86 6920.55,4231.33 6920.22,4231.75 6920,4232.11 6919.92,4232.42 6919.96,4232.67 6920.15,4232.85 6920.5,4232.96 6921,4233 6921,4263 6867.46,4264.03
  region net GM1_DVDDRG: 5684.68,4365.32 5692.13,4372.41 5700.23,4379.35 5708.19,4385.5 5715.83,4390.82 5723.77,4395.74 5731.18,4399.8 5737.99,4403.05 5744.12,4405.58 5749.54,4407.5 5754.98,4409.1 5759.66,4410.22 5764.34,4411.08 5769.01,4411.66 5772.9,4411.93 5776,4412 5776,4442 5726,4427 5649.32,4400.68
  region net GM1_DVDDRG: 5438,4208 5418,4208 ccw(c5212.42,4208) 5353,4358 5503,4358 ccw(c5643.58,4208)
  region net GM1_DVDDRG: 3541.64,6090.29 3544.89,6093.36 3549.12,6096.96 3554.48,6101.01 3560.27,6104.9 3567.32,6109.13 3575.75,6113.61 3585.59,6118.18 3596.84,6122.71 3608.35,6126.64 3619.94,6129.95 3631.4,6132.59 3641.57,6134.36 3650.39,6135.42 3657.88,6135.91 3662.36,6136 3662.36,6186 3660.64,6186.05 3658.01,6186.29 3656.26,6186.56 3654.54,6186.91 3652.9,6187.35 3651.35,6187.87 3649.94,6188.47 3649.29,6188.8 3648.69,6189.15 3648.14,6189.51 3647.64,6189.89 3647.19,6190.29 3646.81,6190.71 3646.49,6191.14 3646.24,6191.59 3646.06,6192.06 3645.96,6192.55 3645.94,6193.04 3646,6193.56 3646.15,6194.09 3646.39,6194.63 3646.73,6195.19 3647.17,6195.77 3647.71,6196.36
  region net ALDO4: 5712.62,5559.82 5709.51,5544.82 ccw(c5709.51,5582.07) 5722.26,5547.07 5722.26,5557.57 ccw(c5712.62,5538.03)
  region net ALDO4: 5675.5,5377.39 5675.47,5377.82 5675.22,5379.06 5673.68,5384.83 5673.42,5386.07 5673.37,5386.49 5673.39,5386.75 5673.5,5386.83 5673.7,5386.7 5684.3,5397.3 5673.3,5397.7 5644.59,5390.2 5655.2,5379.59 5655.59,5379.93 5656.01,5380.2 5656.44,5380.39 5656.88,5380.51 5657.33,5380.56 5657.77,5380.54 5658.2,5380.47 5658.61,5380.33 5659,5380.13 5659.36,5379.88 5659.68,5379.58 5659.96,5379.23 5660.18,5378.84 5660.36,5378.4 5660.46,5377.91 5660.5,5377.39
  region net GM1_DVDDRG: 5888.7,5077.7 5899.3,5088.3 cw(c5901.77,5090.77) 5898.98,5092.87 5882.14,5080.01 cw(c5882.99,5071.99)
  region net GM1_DVDDRG: 5893.61,5493.79 5898.91,5509.7 ccw(c5883.5,5494.29) 5890.5,5514.93 5884.59,5505.98 ccw(c5929.76,5529.94)
  region net CLDO3: 7156.75,5511.08 7139.07,5500.47 7122.07,5469.33 7107.93,5483.47 7128.46,5489.86 7149.68,5518.15
  region net CLDO3: 4886.55,4496.34 4890.03,4499.63 4894.62,4503.53 4899.6,4507.3 4904.9,4510.87 4910.46,4514.17 4915.25,4516.67 4920.12,4518.89 4925.04,4520.8 4928.99,4522.08 4932.93,4523.11 4936.83,4523.87 4939.73,4524.25 4942.58,4524.46 4944.46,4524.5 4944.46,4549.5 4942.96,4549.55 4941.5,4549.69 4940.09,4549.91 4938.73,4550.23 4937.4,4550.63 4936.13,4551.11 4934.9,4551.66 4933.71,4552.29 4932.57,4552.99 4931.48,4553.76 4930.43,4554.6 4929.43,4555.49 4928.47,4556.45 4927.57,4557.46 4926.71,4558.53 4925.5,4560.22 4924.41,4562.02 4923.42,4563.91 4922.54,4565.89 4921.78,4567.93 4921.12,4570.05 4920.57,4572.21 4920.13,4574.42 4919.81,4576.66 4919.6,4578.93 4919.51,4581.21 4919.5,4581.97 4894.5,4581.97 4894.41,4579.01 4894.13,4575.96 4893.49,4571.76 4892.56,4567.44 4891.03,4561.94 4889.12,4556.37 4886.88,4550.81 4883.8,4544.23 4880.38,4537.87 4876.69,4531.83 4873.45,4527.15 4870.11,4522.83 4867.39,4519.7 4865.34,4517.55
  region net GM1_DVDDRG: 5865.21,4415 5864.25,4416.02 5863.35,4417.11 5862.51,4418.25 5861.73,4419.43 5861.02,4420.67 5860.37,4421.94 5859.5,4423.93 5858.78,4425.99 5858.2,4428.12 5857.76,4430.29 5857.45,4432.49 5857.29,4434.72 5857.27,4436.96 5857.38,4439.19 5857.64,4441.41 5858.04,4443.59 5858.57,4445.73 5859.25,4447.81 5860.06,4449.83 5860.68,4451.13 5861.37,4452.38 5862.11,4453.59 5862.92,4454.76 5863.79,4455.87 5864.72,4456.92 5865.21,4457.43 5844,4478.64 5833.39,4446.82 5844,4393.79
  region net GM1_DVDDRG: 5854,4322 5853.88,4317.34 5853.41,4311.51 5852.59,4305.5 5851.41,4299.4 5849.87,4293.31 5848.31,4288.31 5846.5,4283.44 5844.44,4278.75 5842.61,4275.16 5840.62,4271.75 5839.01,4269.32 5837.32,4267.02 5835.53,4264.87 5833.64,4262.86 5854.86,4241.64 5857.74,4244.71 5864.64,4252.87 5866.66,4255.09 5868.26,4256.65 5869.46,4257.67 5870.26,4258.27 5871.06,4258.79 5871.87,4259.23 5872.68,4259.59 5873.09,4259.74 5873.5,4259.86 5873.91,4259.96 5874.33,4260.04 5874.75,4260.09 5875.17,4260.12 5875.59,4260.11 5876.02,4260.09 5876.45,4260.03 5876.89,4259.94 5877.33,4259.83 5877.77,4259.69 5878.22,4259.51 5878.67,4259.31 5879.59,4258.8 5880.52,4258.16 5881.48,4257.39 5882.46,4256.46 5889.54,4263.54 5887.49,4265.7 5886.05,4267.41 5884.77,4269.09 5883.66,4270.75 5882.7,4272.39 5881.88,4274.02 5881.36,4275.23 5880.91,4276.44 5880.53,4277.65 5880.12,4279.25 5879.82,4280.86 5879.62,4282.47 5879.52,4284.09 5879.5,4286.13 5879.6,4288.19 5879.9,4291.13 5880.73,4296.36 5882.98,4308.9 5883.64,4314.32 5883.94,4318.96 5884,4322
  region net CLDO3: 3856.5,5635.5 3856.5,5620.5 ccw(c3856.5,5671.75) 3863.64,5621 3863.64,5635 ccw(c3856.5,5584.25)
  region net CLDO3: 3503.89,5486.75 3489.75,5500.89 3475.61,5472.61 3450,5428.34
  region net GM1_DVDDRG: 6089,4565 6089,4535 6119,4550 6149,4584
  region net CLDO3: 5695.32,4515.36 5677.64,4497.68 5704.16,4488.84 5731,4467.5
  region net GM1_DVDDRG: 6625.42,4482.58 6625.42,4462.58 ccw(c6625.42,4472.58) 6632.56,4465.58 6632.56,4479.58 ccw(c6625.42,4472.58)
内层4:
  region net DCDC3: 3740.54,5600.54 3733.46,5593.46 3734.85,5592.13 3735.25,5591.69 3735.59,5591.22 3735.86,5590.71 3736.05,5590.15 3736.14,5589.51 3744.49,5597.86 3743.85,5597.95 3743.29,5598.14 3742.78,5598.41 3742.31,5598.75 3741.87,5599.15
  region net VDD-SYSFB: 3670,5602.72 3660,5602.72 3660.1,5600.43 3660.1,5599.75 3660.03,5599.1 3659.86,5598.46 3659.56,5597.84 3659.09,5597.21 3670.91,5597.21 3670.44,5597.84 3670.14,5598.46 3669.97,5599.1 3669.9,5599.75 3669.9,5600.43
  region net PWRON: 3694.46,5399.3 3698.7,5403.54 3698.18,5404.15 3697.78,5404.82 3697.47,5405.53 3697.25,5406.28 3697.09,5407.06 3696.91,5408.67 3696.86,5409.49 3688.51,5401.14 3690.14,5401.01 3690.94,5400.91 3691.72,5400.75 3692.47,5400.53 3693.18,5400.22 3693.85,5399.82
  region net RGMII0-RXD3: 6063.01,4507.32 6065.83,4504.5 6066.6,4505.14 6067.34,4505.53 6068.08,4505.72 6068.84,4505.78 6070.5,4505.67 6071.45,4505.62 6072.49,4505.63 6064.14,4513.98 6064.13,4512.94 6064.25,4511.13 6064.29,4510.33 6064.27,4509.95 6064.23,4509.57 6064.16,4509.2 6064.04,4508.83 6063.87,4508.46 6063.65,4508.09 6063.36,4507.71
  region net RGMII0-RXD2: 6045,4502.77 6049,4502.77 6049.09,4503.76 6049.34,4504.57 6049.72,4505.23 6050.22,4505.8 6051.47,4506.9 6052.18,4507.53 6052.91,4508.28 6041.09,4508.28 6041.82,4507.53 6043.19,4506.34 6043.78,4505.8 6044.04,4505.52 6044.28,4505.23 6044.49,4504.91 6044.66,4504.57 6044.81,4504.19 6044.91,4503.76 6044.98,4503.29
  region net RGMII0-RXD2: 6031.34,5427.83 6034.17,5430.66 6033.55,5431.23 6032.39,5432.15 6031.89,5432.58 6031.45,5433.05 6031.11,5433.58 6030.87,5434.23 6030.75,5435.03 6022.4,5426.68 6022.92,5426.68 6023.48,5426.75 6024.06,5426.88 6025.28,5427.25 6027.78,5428.1 6028.38,5428.26 6028.97,5428.37 6029.52,5428.43 6030.04,5428.42 6030.52,5428.32 6030.96,5428.13
  region net RGMII0-RXD3: 6009.36,5425.53 6012.19,5428.36 6011.55,5429.13 6011.16,5429.87 6010.96,5430.61 6010.91,5431.37 6011.02,5433.03 6011.07,5433.97 6011.05,5435.02 6002.7,5426.67 6003.75,5426.65 6005.55,5426.78 6006.35,5426.81 6006.74,5426.8 6007.11,5426.76 6007.49,5426.68 6007.86,5426.56 6008.23,5426.4 6008.6,5426.17 6008.98,5425.89
  region net CPUX-RX: 5835.35,5125.42 5832.52,5128.25 5831.75,5127.61 5831.01,5127.22 5830.27,5127.02 5829.51,5126.97 5827.85,5127.07 5826.91,5127.13 5825.86,5127.11 5834.21,5118.76 5834.23,5119.81 5834.1,5121.61 5834.06,5122.41 5834.08,5122.8 5834.12,5123.17 5834.19,5123.54 5834.31,5123.91 5834.48,5124.28 5834.71,5124.65 5834.99,5125.03
  region net CPUX-TX: 5835.35,5145.09 5832.52,5147.92 5831.75,5147.28 5831.01,5146.89 5830.27,5146.69 5829.51,5146.64 5827.85,5146.75 5826.91,5146.8 5825.86,5146.78 5834.21,5138.43 5834.23,5139.48 5834.1,5141.28 5834.06,5142.08 5834.08,5142.47 5834.12,5142.84 5834.19,5143.21 5834.31,5143.58 5834.48,5143.95 5834.71,5144.33 5834.99,5144.7
  region net LCD0-D21: 5950.27,5109.21 5953.81,5112.75 5953.23,5113.44 5952.83,5114.14 5952.58,5114.87 5952.44,5115.62 5952.38,5116.41 5952.32,5119.05 5943.97,5110.7 5946.61,5110.64 5947.4,5110.58 5948.15,5110.44 5948.88,5110.19 5949.58,5109.79
  region net HTXCN: 5066,4342.87 5062,4342.87 5061.91,4341.92 5061.66,4341.21 5061.28,4340.68 5060.78,4340.26 5059.53,4339.46 5058.82,4338.92 5058.09,4338.21 5069.91,4338.21 5069.54,4338.59 5069.18,4338.92 5068.82,4339.21 5068.13,4339.68 5067.22,4340.26 5066.96,4340.47 5066.72,4340.68 5066.51,4340.93 5066.34,4341.21 5066.19,4341.54 5066.09,4341.92 5066.02,4342.36
  region net HTXCP: 5087,4342.87 5083,4342.87 5082.91,4341.92 5082.66,4341.21 5082.28,4340.68 5081.78,4340.26 5080.53,4339.46 5079.82,4338.92 5079.09,4338.21 5090.91,4338.21 5090.54,4338.59 5090.18,4338.92 5089.82,4339.21 5089.13,4339.68 5088.22,4340.26 5087.96,4340.47 5087.72,4340.68 5087.51,4340.93 5087.34,4341.21 5087.19,4341.54 5087.09,4341.92 5087.02,4342.36
  region net HTX0N: 5123,4342.87 5119,4342.87 5118.91,4341.92 5118.66,4341.21 5118.28,4340.68 5117.78,4340.26 5116.53,4339.46 5115.82,4338.92 5115.09,4338.21 5126.91,4338.21 5126.54,4338.59 5126.18,4338.92 5125.82,4339.21 5125.13,4339.68 5124.22,4340.26 5123.96,4340.47 5123.72,4340.68 5123.51,4340.93 5123.34,4341.21 5123.19,4341.54 5123.09,4341.92 5123.02,4342.36
  region net HTX0P: 5143,4342.87 5139,4342.87 5138.91,4341.92 5138.66,4341.21 5138.28,4340.68 5137.78,4340.26 5136.53,4339.46 5135.82,4338.92 5135.09,4338.21 5146.91,4338.21 5146.54,4338.59 5146.18,4338.92 5145.82,4339.21 5145.13,4339.68 5144.22,4340.26 5143.96,4340.47 5143.72,4340.68 5143.51,4340.93 5143.34,4341.21 5143.19,4341.54 5143.09,4341.92 5143.02,4342.36
  region net HTX1N: 5179,4341.87 5175,4341.87 5174.91,4340.92 5174.66,4340.21 5174.28,4339.68 5173.78,4339.26 5172.53,4338.46 5171.82,4337.92 5171.09,4337.21 5182.91,4337.21 5182.54,4337.59 5182.18,4337.92 5181.82,4338.21 5181.13,4338.68 5180.22,4339.26 5179.96,4339.47 5179.72,4339.68 5179.51,4339.93 5179.34,4340.21 5179.19,4340.54 5179.09,4340.92 5179.02,4341.36
  region net HTX1P: 5199,4340.87 5195,4340.87 5194.87,4340.34 5194.53,4339.83 5194.02,4339.36 5193.41,4338.9 5191.54,4337.62 5191.09,4337.21 5202.91,4337.21 5202.46,4337.62 5200.59,4338.9 5199.98,4339.36 5199.47,4339.83 5199.13,4340.34
  region net HTX2N: 5238,4341.87 5234,4341.87 5233.91,4340.92 5233.66,4340.21 5233.28,4339.68 5232.78,4339.26 5231.53,4338.46 5230.82,4337.92 5230.09,4337.21 5241.91,4337.21 5241.54,4337.59 5241.18,4337.92 5240.82,4338.21 5240.13,4338.68 5239.22,4339.26 5238.96,4339.47 5238.72,4339.68 5238.51,4339.93 5238.34,4340.21 5238.19,4340.54 5238.09,4340.92 5238.02,4341.36
  region net HTX2P: 5258.66,4341.87 5254.66,4341.87 5254.57,4340.92 5254.33,4340.21 5253.94,4339.68 5253.44,4339.26 5252.19,4338.46 5251.49,4337.92 5250.76,4337.21 5262.57,4337.21 5262.2,4337.59 5261.84,4337.92 5261.48,4338.21 5260.8,4338.68 5259.88,4339.26 5259.62,4339.47 5259.38,4339.68 5259.18,4339.93 5259,4340.21 5258.86,4340.54 5258.75,4340.92 5258.69,4341.36
  region net HTX2P: 6318.59,5181.59 6321.41,5184.41 6321.14,5184.87 6321.06,5185.44 6321.12,5186.09 6321.28,5186.79 6321.68,5188.22 6321.82,5188.89 6321.86,5189.49 6313.51,5181.14 6314.11,5181.18 6314.78,5181.32 6316.21,5181.72 6316.91,5181.88 6317.56,5181.94 6318.13,5181.86
  region net HTX2N: 6321.41,5173.59 6318.59,5176.41 6318.13,5176.14 6317.56,5176.06 6316.91,5176.12 6316.21,5176.28 6314.78,5176.68 6314.11,5176.82 6313.51,5176.86 6321.86,5168.51 6321.82,5169.11 6321.68,5169.78 6321.28,5171.21 6321.12,5171.91 6321.06,5172.56 6321.14,5173.13
  region net HTX1P: 6307.72,5141 6307.72,5145 6307.13,5145.08 6306.62,5145.29 6306.18,5145.63 6305.79,5146.08 6305.46,5146.62 6305.16,5147.23 6304.65,5148.62 6303.93,5150.85 6303.66,5151.57 6303.37,5152.26 6303.03,5152.88 6302.65,5153.44 6302.21,5153.91 6302.21,5142.09 6302.74,5142.37 6303.37,5142.39 6304.06,5142.24 6304.81,5141.97 6306.32,5141.33 6307.05,5141.09
  region net HTX1N: 6306.41,5132.59 6303.59,5135.41 6302.85,5134.8 6302.17,5134.47 6301.52,5134.37 6300.87,5134.42 6299.41,5134.73 6298.53,5134.85 6297.51,5134.86 6305.86,5126.51 6305.87,5127.04 6305.85,5127.53 6305.8,5127.98 6305.65,5128.8 6305.42,5129.87 6305.38,5130.2 6305.37,5130.52 6305.4,5130.84 6305.47,5131.17 6305.6,5131.5 6305.8,5131.85 6306.07,5132.21
  region net HTX0N: 6290.41,5096.59 6287.59,5099.41 6286.85,5098.8 6286.17,5098.47 6285.52,5098.37 6284.87,5098.42 6283.41,5098.73 6282.53,5098.85 6281.51,5098.86 6289.86,5090.51 6289.87,5091.04 6289.85,5091.53 6289.8,5091.98 6289.65,5092.8 6289.42,5093.87 6289.38,5094.2 6289.37,5094.52 6289.4,5094.84 6289.47,5095.17 6289.6,5095.5 6289.8,5095.85 6290.07,5096.21
  region net HTX0P: 6292.72,5104.02 6292.72,5108.02 6292.13,5108.09 6291.62,5108.31 6291.18,5108.65 6290.8,5109.09 6290.46,5109.63 6290.16,5110.24 6289.65,5111.63 6288.93,5113.86 6288.66,5114.58 6288.36,5115.26 6288.03,5115.89 6287.65,5116.44 6287.21,5116.91 6287.21,5105.09 6287.74,5105.37 6288.37,5105.4 6289.06,5105.24 6289.81,5104.97 6291.33,5104.34 6292.05,5104.11
  region net HTXCP: 6314.59,5059.59 6317.41,5062.41 6316.8,5063.15 6316.47,5063.83 6316.37,5064.48 6316.42,5065.13 6316.73,5066.59 6316.85,5067.47 6316.86,5068.49 6308.51,5060.14 6309.04,5060.13 6309.53,5060.15 6309.98,5060.2 6310.8,5060.35 6311.87,5060.58 6312.2,5060.62 6312.52,5060.63 6312.84,5060.6 6313.17,5060.53 6313.5,5060.4 6313.85,5060.2 6314.21,5059.93
  region net HTXCN: 6317.41,5051.59 6314.59,5054.41 6313.85,5053.8 6313.17,5053.47 6312.52,5053.37 6311.87,5053.42 6310.41,5053.73 6309.53,5053.85 6308.51,5053.86 6316.86,5045.51 6316.87,5046.04 6316.85,5046.53 6316.8,5046.98 6316.65,5047.8 6316.42,5048.87 6316.38,5049.2 6316.37,5049.52 6316.4,5049.84 6316.47,5050.17 6316.6,5050.5 6316.8,5050.85 6317.07,5051.21
  region net LCD0-D17: 5840.28,4914.5 5840.28,4909.5 5841.18,4909.42 5841.96,4909.21 5842.65,4908.87 5843.28,4908.44 5843.88,4907.92 5845.79,4906.09 5845.79,4917.91 5843.88,4916.08 5843.28,4915.56 5842.65,4915.13 5841.96,4914.79 5841.18,4914.58
  region net LCD0-D16: 5836.5,4965.28 5841.5,4965.28 5841.58,4966.18 5841.79,4966.96 5842.13,4967.65 5842.56,4968.28 5843.08,4968.88 5844.91,4970.79 5833.09,4970.79 5834.92,4968.88 5835.44,4968.28 5835.87,4967.65 5836.21,4966.96 5836.42,4966.18
  region net LCD0-D16: 4495.72,4568.5 4495.72,4573.5 4494.82,4573.58 4494.04,4573.79 4493.35,4574.13 4492.72,4574.56 4492.12,4575.08 4490.21,4576.91 4490.21,4565.09 4492.12,4566.92 4492.72,4567.44 4493.35,4567.87 4494.04,4568.21 4494.82,4568.42
  region net LCD0-D17: 4510.72,4552.5 4510.72,4557.5 4509.82,4557.58 4509.04,4557.79 4508.35,4558.13 4507.72,4558.56 4507.12,4559.08 4505.21,4560.91 4505.21,4549.09 4507.12,4550.92 4507.72,4551.44 4508.35,4551.87 4509.04,4552.21 4509.82,4552.42
  region net LCD0-D18: 4523.72,4536.5 4523.72,4541.5 4522.82,4541.58 4522.04,4541.79 4521.35,4542.13 4520.72,4542.56 4520.12,4543.08 4518.21,4544.91 4518.21,4533.09 4520.12,4534.92 4520.72,4535.44 4521.35,4535.87 4522.04,4536.21 4522.82,4536.42
  region net LCD0-D21: 4567.35,4492.81 4563.81,4496.35 4563.12,4495.77 4562.42,4495.37 4561.69,4495.12 4560.94,4494.98 4560.15,4494.92 4557.51,4494.86 4565.86,4486.51 4565.92,4489.15 4565.98,4489.94 4566.12,4490.69 4566.37,4491.42 4566.77,4492.12
  region net LCD0-D18: 5941.5,5088.28 5946.5,5088.28 5946.58,5089.18 5946.79,5089.96 5947.13,5090.65 5947.56,5091.28 5948.08,5091.88 5949.91,5093.79 5938.09,5093.79 5939.92,5091.88 5940.44,5091.28 5940.87,5090.65 5941.21,5089.96 5941.42,5089.18
  region net LCD0-D19: 5969.28,4855.5 5969.28,4850.5 5969.99,4850.62 5970.72,4850.92 5972.21,4851.75 5972.93,4852.12 5973.61,4852.36 5974.24,4852.37 5974.79,4852.09 5974.79,4863.91 5974.37,4863.46 5974,4862.94 5973.67,4862.35 5973.37,4861.71 5972.33,4858.91 5971.79,4857.61 5971.49,4857.03 5971.15,4856.52 5970.76,4856.1 5970.33,4855.77 5969.84,4855.57
  region net LCD0-D19: 5892.72,4850.5 5892.72,4855.5 5891.82,4855.58 5891.04,4855.79 5890.35,4856.13 5889.72,4856.56 5889.12,4857.08 5887.21,4858.91 5887.21,4847.09 5889.12,4848.92 5889.72,4849.44 5890.35,4849.87 5891.04,4850.21 5891.82,4850.42
  region net USB0-VBUSDET: 6935.3,6116.54 6939.54,6112.3 6940.15,6112.82 6940.82,6113.22 6941.53,6113.53 6942.28,6113.75 6943.06,6113.91 6944.67,6114.09 6945.49,6114.14 6937.14,6122.49 6937.01,6120.86 6936.91,6120.06 6936.75,6119.28 6936.53,6118.53 6936.22,6117.82 6935.82,6117.15
  region net SDC2-DS: 4915.72,4809.5 4915.72,4814.5 4914.82,4814.58 4914.04,4814.79 4913.35,4815.13 4912.72,4815.56 4912.12,4816.08 4910.21,4817.91 4910.21,4806.09 4912.12,4807.92 4912.72,4808.44 4913.35,4808.87 4914.04,4809.21 4914.82,4809.42
  region net SDC2-DS: 5739.5,5128.2 5744.5,5128.2 5744.58,5129.1 5744.79,5129.88 5745.13,5130.57 5745.56,5131.2 5746.08,5131.8 5747.91,5133.72 5736.09,5133.72 5737.92,5131.8 5738.44,5131.2 5738.87,5130.57 5739.21,5129.88 5739.42,5129.1
  region net VDD-SYSFB: 5817.83,5349.05 5824.9,5341.98 5825.34,5342.71 5825.51,5343.61 5825.52,5344.61 5825.41,5346.57 5825.51,5347.37 5825.83,5347.93 5826.49,5348.17 5818.17,5356.49 5818.17,5355.68 5818.46,5352.57 5818.5,5351.5 5818.43,5350.52 5818.23,5349.68
  region net GM0_LED2: 5792.88,4378.12 5797.12,4373.88 5797.66,4374.33 5798.15,4374.56 5798.61,4374.61 5799.07,4374.55 5800.11,4374.28 5800.74,4374.18 5801.49,4374.17 5793.17,4382.49 5793.18,4381.74 5793.28,4381.11 5793.55,4380.07 5793.61,4379.61 5793.56,4379.15 5793.33,4378.66
  region net GM0_LED1: 5819,4383.31 5825,4383.31 5825.06,4384.11 5825.25,4384.86 5825.53,4385.58 5825.9,4386.26 5826.34,4386.93 5827.35,4388.19 5827.89,4388.81 5816.11,4388.81 5817.17,4387.57 5817.66,4386.93 5818.1,4386.26 5818.47,4385.58 5818.75,4384.86 5818.94,4384.11
  region net GM0_LED1: 5625.56,3713.6 5621.32,3709.36 5621.84,3708.75 5622.24,3708.09 5622.55,3707.38 5622.77,3706.63 5622.93,3705.86 5623.11,3704.25 5623.17,3703.43 5631.49,3711.76 5629.86,3711.89 5629.07,3711.99 5628.29,3712.15 5627.54,3712.38 5626.84,3712.68 5626.17,3713.08
  region net GM0_LED2: 5602.56,3713.37 5598.32,3709.12 5598.84,3708.51 5599.24,3707.85 5599.55,3707.14 5599.77,3706.4 5599.93,3705.62 5600.11,3704.01 5600.17,3703.2 5608.49,3711.52 5606.86,3711.65 5606.07,3711.76 5605.29,3711.92 5604.54,3712.14 5603.84,3712.45 5603.17,3712.85
  region net CPUX-RX: 6290,5254 6290,5250 6290.5,5249.87 6290.9,5249.53 6291.24,5249.03 6291.54,5248.42 6292.11,5247.13 6292.43,5246.56 6292.81,5246.11 6292.81,5257.89 6292.43,5257.44 6292.11,5256.87 6291.54,5255.58 6291.24,5254.97 6290.9,5254.47 6290.5,5254.13
  region net CPUX-TX: 6272.03,5253.86 6274.86,5251.03 6275.25,5251.5 6276.51,5253.45 6276.97,5254.09 6277.45,5254.63 6277.96,5255 6278.49,5255.17 6270.17,5263.49 6270.18,5262.9 6270.28,5262.29 6270.45,5261.65 6270.95,5260.34 6272.11,5257.69 6272.34,5257.05 6272.52,5256.44 6272.63,5255.85 6272.65,5255.29 6272.56,5254.77 6272.36,5254.29
  region net CAN-TX0: 5116.97,6018.14 5114.14,6020.97 5113.38,6020.33 5112.64,6019.94 5111.9,6019.75 5111.15,6019.69 5109.49,6019.8 5108.55,6019.85 5107.51,6019.83 5115.83,6011.51 5115.85,6012.55 5115.73,6014.35 5115.69,6015.15 5115.71,6015.53 5115.75,6015.9 5115.82,6016.27 5115.94,6016.64 5116.11,6017.01 5116.33,6017.38 5116.62,6017.76
  region net CAN-RX0: 5095.97,6019.14 5093.14,6021.97 5092.38,6021.33 5091.64,6020.94 5090.9,6020.75 5090.15,6020.69 5088.49,6020.8 5087.55,6020.85 5086.51,6020.83 5094.83,6012.51 5094.85,6013.55 5094.73,6015.35 5094.69,6016.15 5094.71,6016.53 5094.75,6016.9 5094.82,6017.27 5094.94,6017.64 5095.11,6018.01 5095.33,6018.38 5095.62,6018.76
  region net IR-RX: 5073.68,6019.44 5069.44,6023.68 5068.83,6023.16 5068.16,6022.76 5067.46,6022.45 5066.71,6022.23 5065.93,6022.07 5064.33,6021.89 5063.51,6021.83 5071.83,6013.51 5071.96,6015.14 5072.07,6015.93 5072.23,6016.71 5072.45,6017.46 5072.76,6018.16 5073.16,6018.83
  region net USB0-VBUSDET: 5037.68,6020.44 5033.44,6024.68 5032.83,6024.16 5032.16,6023.76 5031.46,6023.45 5030.71,6023.23 5029.93,6023.07 5028.33,6022.89 5027.51,6022.83 5035.83,6014.51 5035.96,6016.14 5036.07,6016.93 5036.23,6017.71 5036.45,6018.46 5036.76,6019.16 5037.16,6019.83
  region net USB0-DRVVBUS: 5014.68,6020.44 5010.44,6024.68 5009.83,6024.16 5009.16,6023.76 5008.46,6023.45 5007.71,6023.23 5006.93,6023.07 5005.33,6022.89 5004.51,6022.83 5012.83,6014.51 5012.96,6016.14 5013.07,6016.93 5013.23,6017.71 5013.45,6018.46 5013.76,6019.16 5014.16,6019.83
  region net CAN-TX0: 7071.31,4462 7071.31,4458 7072.3,4457.91 7073.1,4457.67 7073.76,4457.28 7074.34,4456.79 7075.43,4455.54 7076.06,4454.84 7076.81,4454.11 7076.81,4465.89 7076.06,4465.16 7074.88,4463.8 7074.34,4463.21 7074.06,4462.95 7073.76,4462.72 7073.45,4462.51 7073.1,4462.33 7072.72,4462.19 7072.3,4462.09 7071.83,4462.02
  region net CAN-RX0: 7231,4317.69 7227,4317.69 7226.91,4316.7 7226.67,4315.9 7226.28,4315.24 7225.79,4314.66 7224.54,4313.57 7223.84,4312.94 7223.11,4312.19 7234.89,4312.19 7234.16,4312.94 7232.8,4314.12 7232.21,4314.66 7231.95,4314.94 7231.72,4315.24 7231.51,4315.55 7231.33,4315.9 7231.19,4316.28 7231.09,4316.7 7231.02,4317.17
  region net IR-RX: 7061.68,4099.44 7057.44,4103.68 7056.83,4103.16 7056.16,4102.76 7055.46,4102.45 7054.71,4102.23 7053.93,4102.07 7052.33,4101.89 7051.51,4101.83 7059.83,4093.51 7059.96,4095.14 7060.07,4095.93 7060.23,4096.71 7060.45,4097.46 7060.76,4098.16 7061.16,4098.83
  region net USB0-DRVVBUS: 7016.56,6033.68 7012.32,6029.44 7012.84,6028.83 7013.24,6028.16 7013.55,6027.46 7013.77,6026.71 7013.93,6025.93 7014.11,6024.33 7014.17,6023.51 7022.49,6031.83 7020.86,6031.96 7020.07,6032.07 7019.29,6032.23 7018.54,6032.45 7017.84,6032.76 7017.17,6033.16
  region net PWRON: 4273.56,5380.68 4269.32,5376.44 4269.84,5375.83 4270.24,5375.16 4270.55,5374.46 4270.77,5373.71 4270.93,5372.93 4271.11,5371.33 4271.17,5370.51 4279.49,5378.83 4277.86,5378.96 4277.07,5379.07 4276.29,5379.23 4275.54,5379.45 4274.84,5379.76 4274.17,5380.16
Inner5:
  drawing of 171 lines, arcs and shapes, not listed
GND2:
  region net HP-DET: 5525.7,5711.46 5521.46,5715.7 5520.85,5715.18 5520.18,5714.78 5519.47,5714.47 5518.72,5714.25 5517.94,5714.09 5516.33,5713.91 5515.51,5713.86 5523.86,5705.51 5523.99,5707.14 5524.09,5707.94 5524.25,5708.72 5524.47,5709.47 5524.78,5710.18 5525.18,5710.85
  region net HBIAS: 5511.54,5722.46 5504.46,5729.54 5503.82,5728.95 5503.11,5728.43 5502.33,5728.04 5501.51,5727.86 5509.86,5719.51 5510.04,5720.33 5510.43,5721.11 5510.95,5721.82
  region net HPOUTL: 5493.12,5731.04 5486.04,5738.12 5484.5,5736.43 5484.02,5735.95 5483.51,5735.53 5482.94,5735.2 5482.28,5734.97 5481.51,5734.86 5489.86,5726.51 5489.97,5727.28 5490.2,5727.94 5490.53,5728.51 5490.95,5729.02 5491.43,5729.5
  region net HPOUTFB: 5469.12,5732.04 5462.04,5739.12 5460.5,5737.43 5460.02,5736.95 5459.51,5736.53 5458.94,5736.2 5458.28,5735.97 5457.51,5735.86 5465.86,5727.51 5465.97,5728.28 5466.2,5728.94 5466.53,5729.51 5466.95,5730.02 5467.43,5730.5
  region net HPOUTR: 5441,5731.72 5431,5731.72 5431.1,5729.43 5431.1,5728.75 5431.03,5728.1 5430.86,5727.46 5430.56,5726.84 5430.09,5726.21 5441.91,5726.21 5441.44,5726.84 5441.14,5727.46 5440.97,5728.1 5440.9,5728.75 5440.9,5729.43
  region net HP-DET: 5965.3,6252.54 5969.54,6248.3 5970.15,6248.82 5970.82,6249.22 5971.53,6249.53 5972.28,6249.75 5973.06,6249.91 5974.67,6250.09 5975.49,6250.14 5967.14,6258.49 5967.01,6256.86 5966.91,6256.06 5966.75,6255.28 5966.53,6254.53 5966.22,6253.82 5965.82,6253.15
  region net HBIAS: 5861,6187.28 5871,6187.28 5870.9,6189.57 5870.9,6190.25 5870.97,6190.9 5871.14,6191.54 5871.44,6192.16 5871.91,6192.79 5860.09,6192.79 5860.56,6192.16 5860.86,6191.54 5861.03,6190.9 5861.1,6190.25 5861.1,6189.57
  region net HPOUTL: 5830.88,6173.96 5837.96,6166.88 5839.5,6168.57 5839.98,6169.05 5840.49,6169.47 5841.06,6169.8 5841.72,6170.03 5842.49,6170.14 5834.14,6178.49 5834.03,6177.72 5833.8,6177.06 5833.47,6176.49 5833.05,6175.98 5832.57,6175.5
  region net HPOUTFB: 5802.88,6183.96 5809.96,6176.88 5811.5,6178.57 5811.98,6179.05 5812.49,6179.47 5813.06,6179.8 5813.72,6180.03 5814.49,6180.14 5806.14,6188.49 5806.03,6187.72 5805.8,6187.06 5805.47,6186.49 5805.05,6185.98 5804.57,6185.5
  region net HPOUTR: 5764.88,6174.96 5771.96,6167.88 5773.5,6169.57 5773.98,6170.05 5774.49,6170.47 5775.06,6170.8 5775.72,6171.03 5776.49,6171.14 5768.14,6179.49 5768.03,6178.72 5767.8,6178.06 5767.47,6177.49 5767.05,6176.98 5766.57,6176.5
Bottom Layer:
  drawing of 707 lines, arcs and shapes, not listed

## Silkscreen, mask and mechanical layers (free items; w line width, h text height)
Top Silkscreen Layer:
  text "OTG&D" at 6451.76,6394.09 h51.92 r270
  text "AUDIO" at 5884.76,6388.99 h51.92 r270
  text "GPIO" at 3597.29,6124.76 h51.92
  text "Allwinner T527" at 5554.18,5715.54 h45.43
  text "LPDDR4" at 4625.14,5632.54 h45.43
  text "ON" at 4382.85,5264.76 h51.92
  text "拆拆我的" at 4858.46,5205.25 h67.97 r90
  text "RESET" at 4310.01,4978.76 h51.92
  text "FAN" at 4122.68,4862.32 h38.94
  text "eMMC" at 4615.46,4796.13 h45.43 r90
  text "Avaota A1" at 5210,4733 h270
  text "FEL" at 4366.57,4681.76 h51.92
  text "CAN" at 7033.24,4348.57 h51.92 r90
  text "RGB LED" at 3566.76,4213.55 h51.92 r270
  text "ETH0" at 6836.29,4159.76 h51.92
  text "ETH1" at 6138.29,4155.76 h51.92
  text "IR" at 7198.85,3771.76 h51.92
  text "12VDC" at 4098.76,3726.99 h51.92 r270
  text "HDMI" at 5222.76,3666.71 h51.92 r270
  text "USB" at 4811.76,3648.43 h51.92 r270
  text "DP" at 5594.76,3590.15 h51.92 r270
Bottom Silkscreen Layer:
  circle w20 net "": c3771,4980 r27
  circle w20 net "": c6984,4528 r27
  text "BIOS" at 5703.22,6127.99 h29.2
  text "TFCard/JTAG" at 6797.32,6031 h38.94 r90
  text "Avaota A1" at 4897,5548 h270
  text "OV13850" at 7057.32,5244.16 h38.94 r90
  text "RGB888/LVDS/MIPI DSI/JTAG /  UART/IIC/I2S/SPI/PWM  MUX" at 3747.32,4989.1 h43.41 r90
  text "v1.3" at 7214.18,3724.24 h38.94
